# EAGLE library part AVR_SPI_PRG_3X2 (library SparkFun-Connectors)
AVR ISP 6 Pin This is the reduced ISP connector for AVR programming. Common on Arduino. This footprint will take up less PCB space and can be used with a 10-pin to 6-pin adapter such as SKU: BOB-08508 **Special note about "TEST_POINT" package. The stop mask is on the top side, so if you want your programming test points to be on the bottom of your board, make sure to place this package on the bottom side of the board. This also ensure that the orientation to program from the bottom side will be correct.

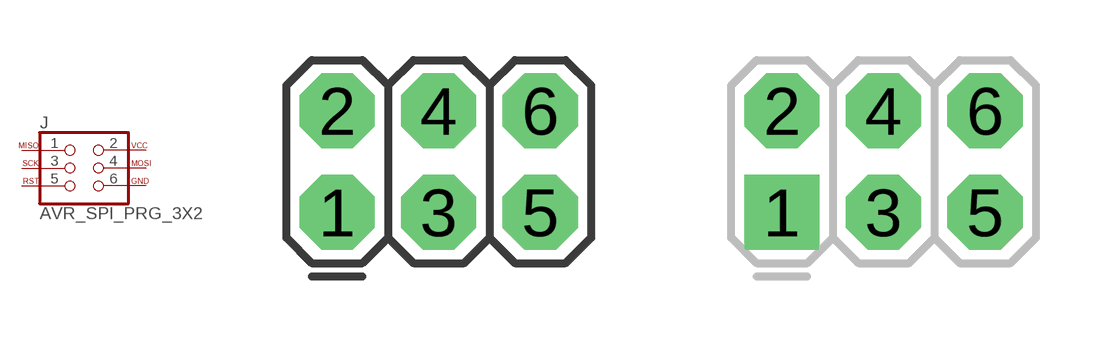
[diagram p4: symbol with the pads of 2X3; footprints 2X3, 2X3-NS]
Designator prefix J

## AVR_SPI_PRG_3X2PTH  [2X3]
1  1  pas
2  2  pas
3  3  pas
4  4  pas
5  5  pas
6  6  pas

## AVR_SPI_PRG_3X2NS  [2X3-NS]
Pads as for 2X3

## AVR_SPI_PRG_3X2OFFSET_PADS  [2X3_OFFSET]
Pads as for 2X3

## AVR_SPI_PRG_3X22X3_LOCK  [2X3_LOCK]
Pads as for 2X3

## AVR_SPI_PRG_3X2TESTPOINTS  [2X3_TEST_POINTS]
Pads as for 2X3

## Footprint 2X3 (pad centres in mm)
drill 1.016 pad 1.88 octagon: 1 0,0; 2 0,2.54; 3 2.54,0; 4 2.54,2.54; 5 5.08,0; 6 5.08,2.54

## Footprint 2X3-NS (pad centres in mm)
drill 1.016 pad 1.88 square: 1 -2.54,-1.27
drill 1.016 pad 1.88 octagon: 2 -2.54,1.27; 3 0,-1.27; 4 0,1.27; 5 2.54,-1.27; 6 2.54,1.27

## Footprint 2X3_OFFSET (pad centres in mm)
drill 1.118 pad 1.88 offset: 1 -2.54,-1.27; 2 -2.54,1.27; 3 0,-1.27; 4 0,1.27; 5 2.54,-1.27; 6 2.54,1.27

## Footprint 2X3_LOCK (pad centres in mm)
drill 1.016 pad 1.88 octagon: 1 0,0; 2 0,2.54; 3 2.54,-0.254; 4 2.54,2.286; 5 5.08,0; 6 5.08,2.54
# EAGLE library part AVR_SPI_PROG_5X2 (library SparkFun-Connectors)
AVR 10-pin ICSP Header This is the standard AVR In Circuit Serial Programming header. Minimal, but includes pin one indicator. Works with standard Olimex programmers. Also look for the 6-pin reduced version. Spark Fun Electronics SKU: PRT-00778

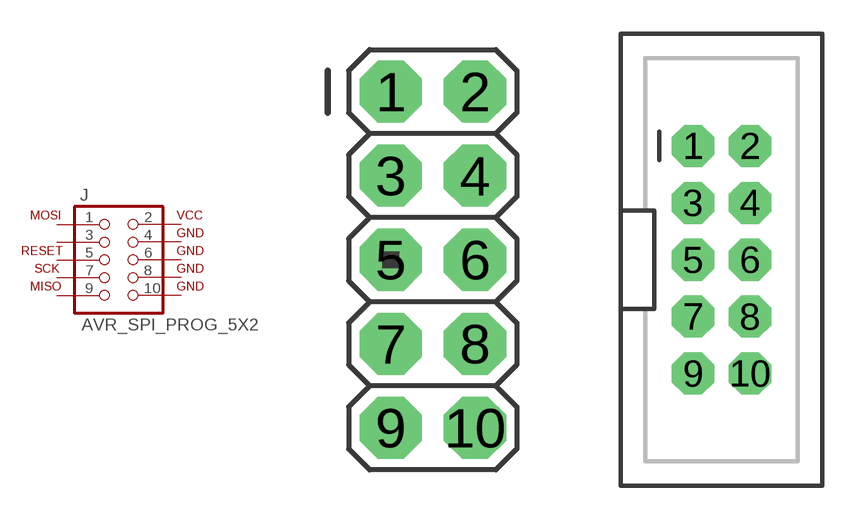
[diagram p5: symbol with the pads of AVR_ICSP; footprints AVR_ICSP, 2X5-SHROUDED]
Designator prefix J

## AVR_SPI_PROG_5X2PTH  [AVR_ICSP]
1  MOSI  pas
2  VCC  pwr
3  NC  nc
4  GND  pwr
5  RESET  pas
6  GND  pwr
7  SCK  pas
8  GND  pwr
9  MISO  pas
10  GND  pwr

## AVR_SPI_PROG_5X2PTH2  [2X5-SHROUDED]
Pads as for AVR_ICSP

## AVR_SPI_PROG_5X2LOCK  [2X5-SHROUDED_LOCK]
Pads as for AVR_ICSP

## AVR_SPI_PROG_5X2SMD  [2X5-SHROUDED_SMD]
Pads as for AVR_ICSP

## Footprint AVR_ICSP (pad centres in mm)
PIN HEADER
drill 1.016 pad 1.88 octagon: 1 -1.27,5.08; 2 1.27,5.08; 3 -1.27,2.54; 4 1.27,2.54; 5 -1.27,0; 6 1.27,0; 7 -1.27,-2.54; 8 1.27,-2.54; 9 -1.27,-5.08; 10 1.27,-5.08

## Footprint 2X5-SHROUDED (pad centres in mm)
drill 1.016 pad 1.88 octagon: 1 -1.27,5.08; 2 1.27,5.08; 3 -1.27,2.54; 4 1.27,2.54; 5 -1.27,0; 6 1.27,0; 7 -1.27,-2.54; 8 1.27,-2.54; 9 -1.27,-5.08; 10 1.27,-5.08

## Footprint 2X5-SHROUDED_LOCK (pad centres in mm)
drill 1.016 pad 1.88 octagon: 1 -1.397,5.08; 2 1.397,5.08; 3 -1.397,2.54; 4 1.397,2.54; 5 -1.397,0; 6 1.397,0; 7 -1.397,-2.54; 8 1.397,-2.54; 9 -1.397,-5.08; 10 1.397,-5.08

## Footprint 2X5-SHROUDED_SMD (pad centres in mm)
smd 4.15 x 1: 1 -2.794,5.08; 2 2.794,5.08; 3 -2.794,2.54; 4 2.794,2.54; 5 -2.794,0; 6 2.794,0; 7 -2.794,-2.54; 8 2.794,-2.54; 9 -2.794,-5.08; 10 2.794,-5.08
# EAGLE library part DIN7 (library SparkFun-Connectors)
Mini-DIN7 connector

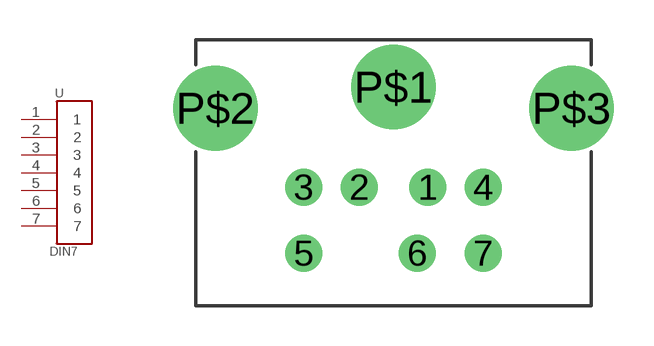
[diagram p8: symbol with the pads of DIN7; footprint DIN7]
Designator prefix -

## DIN7  [DIN7]
1  1
2  2
3  3
4  4
5  5
6  6
7  7

## Footprint DIN7 (pad centres in mm)
drill 0.9: 1 1.3,-3.8; 2 -1.3,-3.8; 3 -3.4,-3.8; 4 3.4,-3.8; 5 -3.4,-6.3; 6 0.9,-6.3; 7 3.4,-6.3
drill 2.2: P$1 0,0; P$2 -6.75,-0.8; P$3 6.75,-0.8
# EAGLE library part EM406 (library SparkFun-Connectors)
EM406 GPS Connector Proven layout and schematic for EM406 connector. Spark Fun Electronics SKU : GPS-00579

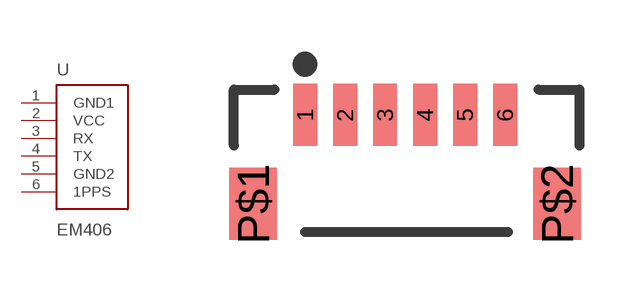
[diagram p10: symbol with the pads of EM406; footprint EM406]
Designator prefix U

## EM406  [EM406]
1  GND1
2  VCC
3  RX
4  TX
5  GND2
6  1PPS

## Footprint EM406 (pad centres in mm)
smd 0.6 x 1.55: 1 0,0; 2 1,0; 3 2,0; 4 3,0; 5 4,0; 6 5,0
smd 1.2 x 1.8: P$1 -1.3,-2.225; P$2 6.3,-2.225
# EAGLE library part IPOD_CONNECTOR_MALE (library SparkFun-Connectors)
iPod Male Connector This is the connector that will insert into an iPods. Use this connector to gain access to the various iPod pins. Schematic and footprint are not yet production proven. The PCB thickness must be more thin than the standard 0.062" FR4. Spark Fun Electronics SKU : DEV-00633

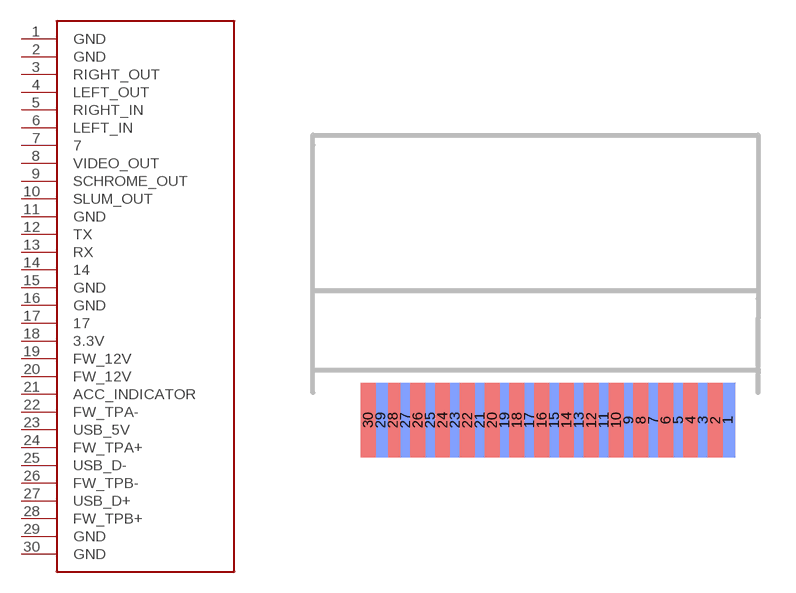
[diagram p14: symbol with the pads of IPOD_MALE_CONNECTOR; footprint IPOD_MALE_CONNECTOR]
Designator prefix -

## IPOD_CONNECTOR_MALE  [IPOD_MALE_CONNECTOR]
1  GND
2  GND
3  RIGHT_OUT
4  LEFT_OUT
5  RIGHT_IN
6  LEFT_IN
7  7
8  VIDEO_OUT
9  SCHROME_OUT
10  SLUM_OUT
11  GND
12  TX
13  RX
14  14
15  GND
16  GND
17  17
18  3.3V
19  FW_12V
20  FW_12V
21  ACC_INDICATOR
22  FW_TPA-
23  USB_5V
24  FW_TPA+
25  USB_D-
26  FW_TPB-
27  USB_D+
28  FW_TPB+
29  GND
30  GND

## Footprint IPOD_MALE_CONNECTOR (pad centres in mm)
smd 0.6 x 3 bottom: 1 7.5,0; 3 6.5,0; 5 5.5,0; 7 4.5,0; 9 3.5,0; 11 2.5,0; 13 1.5,0; 15 0.5,0; 17 -0.5,0; 19 -1.5,0; 21 -2.5,0; 23 -3.5,0; 25 -4.5,0; 27 -5.5,0; 29 -6.5,0
smd 0.6 x 3: 2 7,0; 4 6,0; 6 5,0; 8 4,0; 10 3,0; 12 2,0; 14 1,0; 16 0,0; 18 -1,0; 20 -2,0; 22 -3,0; 24 -4,0; 26 -5,0; 28 -6,0; 30 -7,0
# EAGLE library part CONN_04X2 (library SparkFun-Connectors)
.1" header, two rows of four.

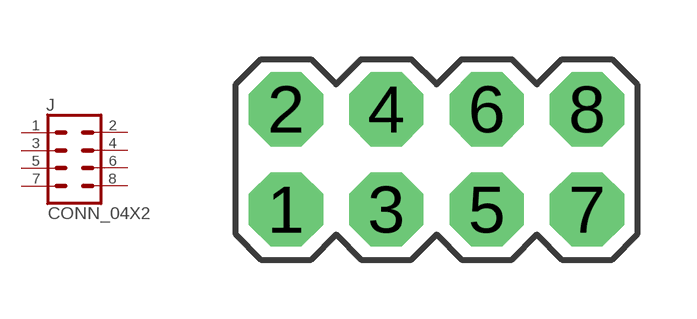
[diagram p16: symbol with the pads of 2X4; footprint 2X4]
Designator prefix J

## CONN_04X2  [2X4]
1  1  pas
2  2  pas
3  3  pas
4  4  pas
5  5  pas
6  6  pas
7  7  pas
8  8  pas

## Footprint 2X4 (pad centres in mm)
drill 1.016 pad 1.88 octagon: 1 -3.81,-1.27; 2 -3.81,1.27; 3 -1.27,-1.27; 4 -1.27,1.27; 5 1.27,-1.27; 6 1.27,1.27; 7 3.81,-1.27; 8 3.81,1.27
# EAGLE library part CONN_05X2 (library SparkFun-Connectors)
Header 5x2 Standard 10-pin dual row 0.1" header. Commonly used with AVR-ISP. Use with Spark Fun Electronics SKU: PRT-00778

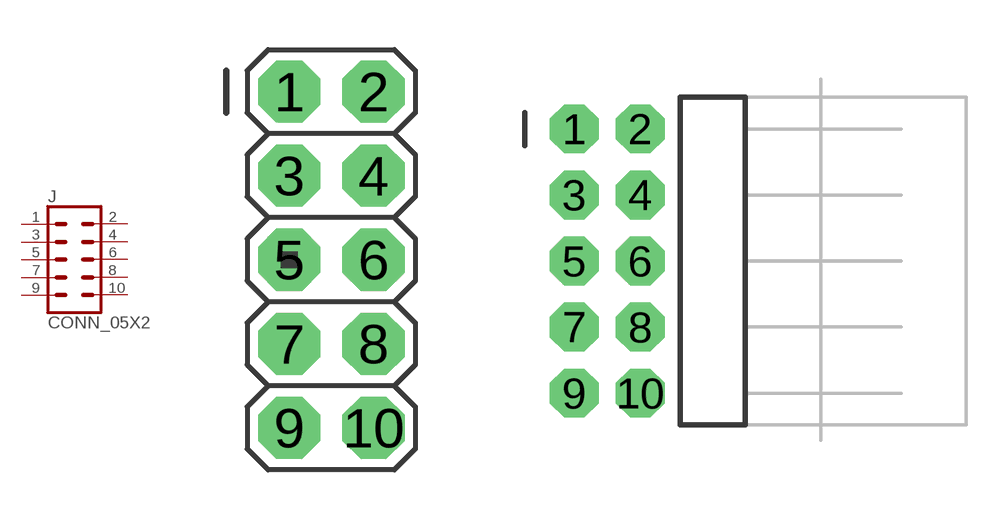
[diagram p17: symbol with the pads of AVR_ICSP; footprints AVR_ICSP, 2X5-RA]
Designator prefix J

## CONN_05X2PTH  [AVR_ICSP]
1  1  pas
2  2  pas
3  3  pas
4  4  pas
5  5  pas
6  6  pas
7  7  pas
8  8  pas
9  9  pas
10  10  pas

## CONN_05X2RA  [2X5-RA]
Pads as for AVR_ICSP

## CONN_05X2RAF  [2X5-RAF]
Pads as for AVR_ICSP

## CONN_05X2SHD  [2X5-SHROUDED]
Pads as for AVR_ICSP

## CONN_05X2SHD_LOCK  [2X5-SHROUDED_LOCK]
Pads as for AVR_ICSP

## CONN_05X2SHD_SMD  [2X5-SHROUDED_SMD]
Pads as for AVR_ICSP

## CONN_05X2NO_SILK  [2X5_NOSILK]
Pads as for AVR_ICSP

## CONN_05X20.05_IN_PTH_SILK  [2X5_PTH_SILK_.05]
Pads as for AVR_ICSP

## CONN_05X2SHD-NS  [2X5-SHROUDED-NS]
Pads as for AVR_ICSP

## Footprint AVR_ICSP (pad centres in mm)
PIN HEADER
drill 1.016 pad 1.88 octagon: 1 -1.27,5.08; 2 1.27,5.08; 3 -1.27,2.54; 4 1.27,2.54; 5 -1.27,0; 6 1.27,0; 7 -1.27,-2.54; 8 1.27,-2.54; 9 -1.27,-5.08; 10 1.27,-5.08

## Footprint 2X5-RA (pad centres in mm)
drill 1.016 pad 1.88 octagon: 1 -1.27,5.08; 2 1.27,5.08; 3 -1.27,2.54; 4 1.27,2.54; 5 -1.27,0; 6 1.27,0; 7 -1.27,-2.54; 8 1.27,-2.54; 9 -1.27,-5.08; 10 1.27,-5.08

## Footprint 2X5-RAF (pad centres in mm)
drill 1.016 pad 1.88 octagon: 1 -1.27,5.08; 2 1.27,5.08; 3 -1.27,2.54; 4 1.27,2.54; 5 -1.27,0; 6 1.27,0; 7 -1.27,-2.54; 8 1.27,-2.54; 9 -1.27,-5.08; 10 1.27,-5.08

## Footprint 2X5-SHROUDED (pad centres in mm)
drill 1.016 pad 1.88 octagon: 1 -1.27,5.08; 2 1.27,5.08; 3 -1.27,2.54; 4 1.27,2.54; 5 -1.27,0; 6 1.27,0; 7 -1.27,-2.54; 8 1.27,-2.54; 9 -1.27,-5.08; 10 1.27,-5.08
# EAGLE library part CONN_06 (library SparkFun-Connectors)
Header 6 Standard 6-pin 0.1" header. Use with straight break away headers (SKU : PRT-00116), right angle break away headers (PRT-00553), swiss pins (PRT-00743), machine pins (PRT-00117), and female headers (PRT-00115). Molex polarized connector foot print use with SKU : PRT-08094 with associated crimp pins and housings. NOTES ON THE VARIANTS LOCK and LOCK_LONGPADS... This footprint was designed to help hold the alignment of a through-hole component (i.e. 6-pin header) while soldering it into place. You may notice that each hole has been shifted either up or down by 0.005 of an inch from it's more standard position (which is a perfectly straight line). This slight alteration caused the pins (the squares in the middle) to touch the edges of the holes. Because they are alternating, it causes a "brace" to hold the component in place. 0.005 has proven to be the perfect amount of "off-center" position when using our standard breakaway headers. Although looks a little odd when you look at the bare footprint, once you have a header in there, the alteration is very hard to notice. Also,if you push a header all the way into place, it is covered up entirely on the bottom side. This idea of altering the position of holes to aid alignment will be further integrated into the Sparkfun Library for other footprints. It can help hold any component with 3 or more connection pins.

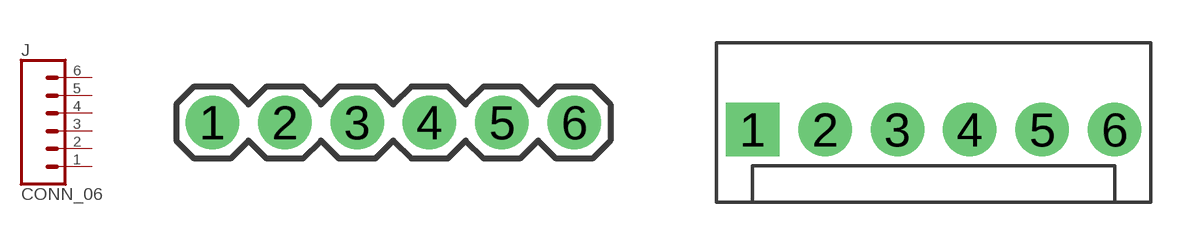
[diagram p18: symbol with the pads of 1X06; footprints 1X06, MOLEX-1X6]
Designator prefix J

## CONN_06SILK_FEMALE_PTH (PROD_ID: CONN-08437)  [1X06]
1  1  pas
2  2  pas
3  3  pas
4  4  pas
5  5  pas
6  6  pas

## CONN_06POLAR  [MOLEX-1X6]
Pads as for 1X06

## CONN_06RA  [MOLEX-1X6-RA]
Pads as for 1X06

## CONN_06SMD (PROD_ID: CONN-08971; VALUE: RA 6Pin SMD)  [1X06-SMD]
Pads as for 1X06

## CONN_06LOCK  [1X06_LOCK]
Pads as for 1X06

## CONN_06LOCK_LONGPADS  [1X06_LOCK_LONGPADS]
Pads as for 1X06

## CONN_06POLAR_LOCK  [MOLEX-1X6_LOCK]
Pads as for 1X06

## CONN_06RA_LOCK  [MOLEX-1X6-RA_LOCK]
Pads as for 1X06

## CONN_06SIP_LOCK  [1X06-SIP_LOCK]
Pads as for 1X06

## CONN_06FEMALE_LOCK  [1X06_FEMALE_LOCK.010]
Pads as for 1X06

## CONN_06LONGPADS  [1X06_LONGPADS]
Pads as for 1X06

## CONN_061X06-SMD_EDGE_FEMALE  [1X06-SMD_EDGE]
Pads as for 1X06

## CONN_063.5MM-6  [SCREWTERMINAL-3.5MM-6]
Pads as for 1X06

## CONN_06SMDF  [1X06-SMD-FEMALE]
Pads as for 1X06

## CONN_06SMD-FEMALE-V2 (PROD_ID: CONN-09668)  [1X06-SMD-FEMALE-V2]
Pads as for 1X06

## CONN_06POGOPIN_HOLES_ONLY (PROD_ID: CONN-08437)  [1X06_HOLES_ONLY]
Pads as for 1X06

## CONN_06SMD-STRAIGHT-FEMALE (PROD_ID: CONN-10203)  [1X06_SMD_STRAIGHT]
Pads as for 1X06

## CONN_06SMD-STRAIGHT-ALT-FEMALE (PROD_ID: CONN-10203)  [1X06_SMD_STRAIGHT_ALT]
Pads as for 1X06

## CONN_06SMD-STRAIGHT-COMBO-FEMALE (PROD_ID: CONN-10203)  [1X06_SMD_STRAIGHT_COMBO]
Pads as for 1X06

## CONN_06VERNIER-ANALOG  [BTA]
Pads as for 1X06

## CONN_06VERNIER-DIGITAL  [BTD]
Pads as for 1X06

## CONN_06SMD_MALE (PROD_ID: CONN-11293)  [1X06_SMD_MALE]
Pads as for 1X06

## CONN_06SMD-1MM  [1X06-1MM]
Pads as for 1X06

## CONN_06NO_SILK_FEMALE_PTH (PROD_ID: CONN-08437)  [1X06_NO_SILK]
Pads as for 1X06

## CONN_06NO_SILK_YES_STOP  [1X06_NO_SILK_YES_STOP]
Pads as for 1X06

## CONN_061.27MM  [1X06-1.27MM]
Pads as for 1X06

## Footprint 1X06 (pad centres in mm)
drill 1.016 pad 1.88: 1 0,0; 2 2.54,0; 3 5.08,0; 4 7.62,0; 5 10.16,0; 6 12.7,0

## Footprint MOLEX-1X6 (pad centres in mm)
drill 1.016 pad 1.88 square: 1 0,0
drill 1.016 pad 1.88: 2 2.54,0; 3 5.08,0; 4 7.62,0; 5 10.16,0; 6 12.7,0

## Footprint MOLEX-1X6-RA (pad centres in mm)
drill 1.016 pad 1.88 square: 1 0,0
drill 1.016 pad 1.88: 2 2.54,0; 3 5.08,0; 4 7.62,0; 5 10.16,0; 6 12.7,0

## Footprint 1X06-SMD (pad centres in mm)
smd 1 x 3: 1 -6.35,5; 2 -3.81,5; 3 -1.27,5; 4 1.27,5; 5 3.81,5; 6 6.35,5
hole 1.4 at -5.08,0
hole 1.4 at 5.08,0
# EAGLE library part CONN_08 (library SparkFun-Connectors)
Header 8 Standard 8-pin 0.1" header. Use with straight break away headers (SKU : PRT-00116), right angle break away headers (PRT-00553), swiss pins (PRT-00743), machine pins (PRT-00117), and female headers (PRT-00115).

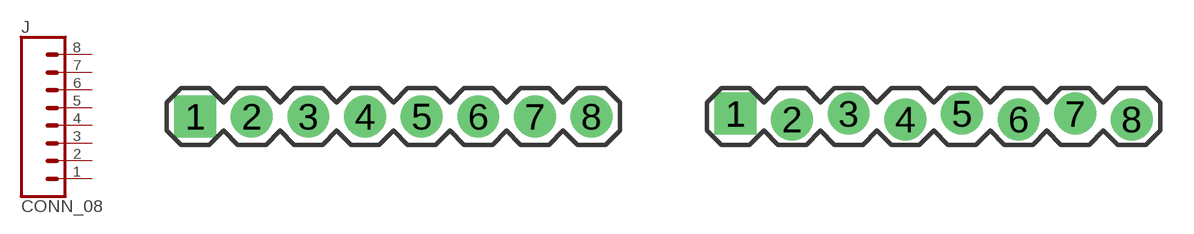
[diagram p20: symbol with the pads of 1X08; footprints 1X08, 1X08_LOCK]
Designator prefix J

## CONN_08SILK_FEMALE_PTH (PROD_ID: CONN-08438)  [1X08]
1  1  pas
2  2  pas
3  3  pas
4  4  pas
5  5  pas
6  6  pas
7  7  pas
8  8  pas

## CONN_08LOCK  [1X08_LOCK]
Pads as for 1X08

## CONN_08LOCK_LONGPADS  [1X08_LOCK_LONGPADS]
Pads as for 1X08

## CONN_08LONGPADS  [1X08_LONGPADS]
Pads as for 1X08

## CONN_083.5MM-8  [SCREWTERMINAL-3.5MM-8]
Pads as for 1X08

## CONN_08SMD-STRAIGHT-FEMALE (PROD_ID: CONN-10204)  [1X08_SMD]
Pads as for 1X08

## CONN_08SMD-STRAIGHT-ALT-FEMALE (PROD_ID: CONN-10204)  [1X08_SMD_ALT]
Pads as for 1X08

## CONN_08SMD-COMBO-FEMALE (PROD_ID: CONN-10204)  [1X08_SMD_COMBINED]
Pads as for 1X08

## CONN_08BM08B-SRSS-TB  [BM08B-SRSS-TB]
Pads as for 1X08

## CONN_08SMD-MALE (PROD_ID: CONN-11292)  [1X08_SMD_MALE]
Pads as for 1X08

## CONN_08NO_SILK_FEMALE_PTH (PROD_ID: CONN-08438)  [1X08_NO_SILK]
Pads as for 1X08

## CONN_08NO_SILK  [1X08_PIN1_NO_SILK]
Pads as for 1X08

## CONN_08 (PROD_ID: CONN-08437)  [1X08_ROUND]
Pads as for 1X08

## CONN_08LOCK_NO_SILK  [1X08_LOCK_NO_SILK]
Pads as for 1X08

## CONN_08FEMALE_LOCK  [1X08_FEMALE_LOCK]
Pads as for 1X08

## Footprint 1X08 (pad centres in mm)
drill 1.016 pad 1.88 square: 1 0,0
drill 1.016 pad 1.88: 2 2.54,0; 3 5.08,0; 4 7.62,0; 5 10.16,0; 6 12.7,0; 7 15.24,0; 8 17.78,0

## Footprint 1X08_LOCK (pad centres in mm)
drill 1.016 pad 1.88 square: 1 0,0.127
drill 1.016 pad 1.88: 2 2.54,-0.127; 3 5.08,0.127; 4 7.62,-0.127; 5 10.16,0.127; 6 12.7,-0.127; 7 15.24,0.127; 8 17.78,-0.127

## Footprint 1X08_LOCK_LONGPADS (pad centres in mm)
drill 1.016 long: 1 0,0.127; 2 2.54,-0.127; 3 5.08,0.127; 4 7.62,-0.127; 5 10.16,0.127; 6 12.7,-0.127; 7 15.24,0.127; 8 17.78,-0.127

## Footprint 1X08_LONGPADS (pad centres in mm)
drill 1.118 pad 1.88 long: 1 0,0; 2 2.54,0; 3 5.08,0; 4 7.62,0; 5 10.16,0; 6 12.7,0; 7 15.24,0; 8 17.78,0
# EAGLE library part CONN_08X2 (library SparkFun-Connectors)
.1" headers, two rows of 8 each

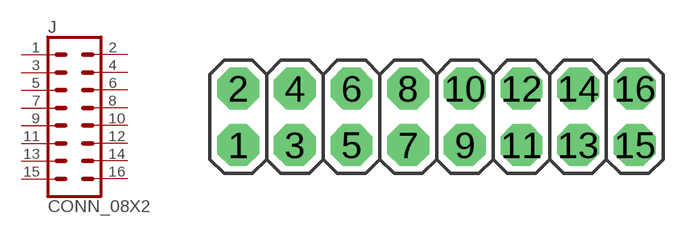
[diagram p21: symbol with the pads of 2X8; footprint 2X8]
Designator prefix J

## CONN_08X2  [2X8]
1  1  pas
2  2  pas
3  3  pas
4  4  pas
5  5  pas
6  6  pas
7  7  pas
8  8  pas
9  9  pas
10  10  pas
11  11  pas
12  12  pas
13  13  pas
14  14  pas
15  15  pas
16  16  pas

## Footprint 2X8 (pad centres in mm)
drill 1.016 pad 1.88 octagon: 1 0,0; 2 0,2.54; 3 2.54,0; 4 2.54,2.54; 5 5.08,0; 6 5.08,2.54; 7 7.62,0; 8 7.62,2.54; 9 10.16,0; 10 10.16,2.54; 11 12.7,0; 12 12.7,2.54; 13 15.24,0; 14 15.24,2.54; 15 17.78,0; 16 17.78,2.54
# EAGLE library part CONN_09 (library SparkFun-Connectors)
Header 9 Standard 9-pin 0.1" header. Use with straight break away headers (SKU : PRT-00116), right angle break away headers (PRT-00553), swiss pins (PRT-00743), machine pins (PRT-00117), and female headers (PRT-00115).

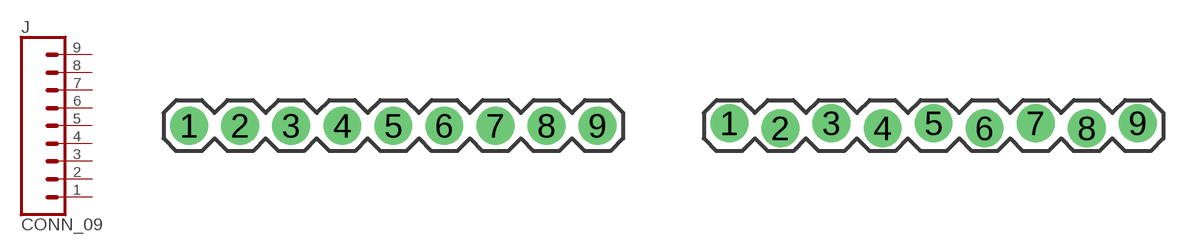
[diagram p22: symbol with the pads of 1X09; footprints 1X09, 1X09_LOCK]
Designator prefix J

## CONN_09  [1X09]
1  1  pas
2  2  pas
3  3  pas
4  4  pas
5  5  pas
6  6  pas
7  7  pas
8  8  pas
9  9  pas

## CONN_09LOCK  [1X09_LOCK]
Pads as for 1X09

## CONN_09LOCK-LONGPADS  [1X09_LOCK_LONGPADS]
Pads as for 1X09

## CONN_09LONGPADS  [1X09_LONGPADS]
Pads as for 1X09

## CONN_09NO_SILK  [1X09_NO_SILK]
Pads as for 1X09

## Footprint 1X09 (pad centres in mm)
drill 1.016 pad 1.88: 1 0,0; 2 2.54,0; 3 5.08,0; 4 7.62,0; 5 10.16,0; 6 12.7,0; 7 15.24,0; 8 17.78,0; 9 20.32,0

## Footprint 1X09_LOCK (pad centres in mm)
drill 1.016 pad 1.88: 1 0,0.127; 2 2.54,-0.127; 3 5.08,0.127; 4 7.62,-0.127; 5 10.16,0.127; 6 12.7,-0.127; 7 15.24,0.127; 8 17.78,-0.127; 9 20.32,0.127

## Footprint 1X09_LOCK_LONGPADS (pad centres in mm)
drill 1.016 long: 1 0,0.127; 2 2.54,-0.127; 3 5.08,0.127; 4 7.62,-0.127; 5 10.16,0.127; 6 12.7,-0.127; 7 15.24,0.127; 8 17.78,-0.127; 9 20.32,0.127

## Footprint 1X09_LONGPADS (pad centres in mm)
drill 1.118 pad 1.88 long: 1 0,0; 2 2.54,0; 3 5.08,0; 4 7.62,0; 5 10.16,0; 6 12.7,0; 7 15.24,0; 8 17.78,0; 9 20.32,0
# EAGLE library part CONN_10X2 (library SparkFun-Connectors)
This was SPECIALLY designed to be used with our Graphic LCD Backpack. Be sure you want to use this! It is not only staggered on each line of header holes, but IT IS ALSO offset of the center point of the top and bottom lines by 5 mil. This causes the headers to lock into place on the "standard" footprint on the LCD screen. The extra squares on the tdocu layer are there simply to reference other pins (if you were to actually populate a longer header than ten long - this is what we do with the backpacks).

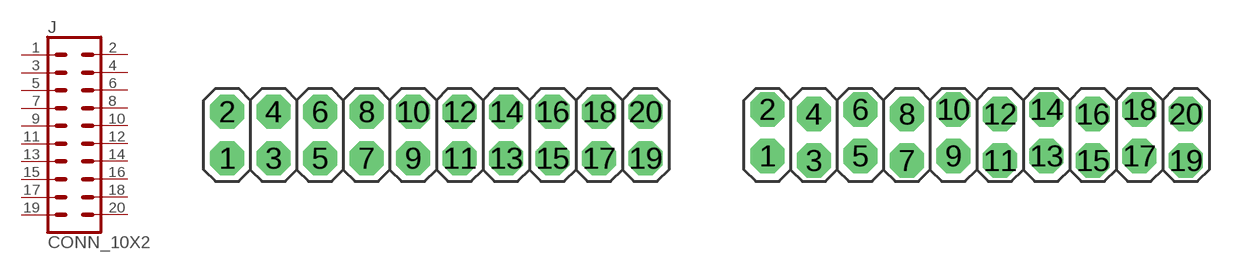
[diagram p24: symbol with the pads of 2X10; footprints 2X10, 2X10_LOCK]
Designator prefix J

## CONN_10X2  [2X10]
1  1  pas
2  2  pas
3  3  pas
4  4  pas
5  5  pas
6  6  pas
7  7  pas
8  8  pas
9  9  pas
10  10  pas
11  11  pas
12  12  pas
13  13  pas
14  14  pas
15  15  pas
16  16  pas
17  17  pas
18  18  pas
19  19  pas
20  20  pas

## CONN_10X22X10_LOCK  [2X10_LOCK]
Pads as for 2X10

## CONN_10X2SPECIAL  [2X10_LOCK_SPECIAL]
Pads as for 2X10

## CONN_10X2NOSILK  [2X10_NOSILK]
Pads as for 2X10

## CONN_10X2ROUND_NOSILK  [2X10_ROUND_NOSILK]
Pads as for 2X10

## Footprint 2X10 (pad centres in mm)
PIN HEADER
drill 1.016 pad 1.88 octagon: 1 -11.43,-1.27; 2 -11.43,1.27; 3 -8.89,-1.27; 4 -8.89,1.27; 5 -6.35,-1.27; 6 -6.35,1.27; 7 -3.81,-1.27; 8 -3.81,1.27; 9 -1.27,-1.27; 10 -1.27,1.27; 11 1.27,-1.27; 12 1.27,1.27; 13 3.81,-1.27; 14 3.81,1.27; 15 6.35,-1.27; 16 6.35,1.27; 17 8.89,-1.27; 18 8.89,1.27; 19 11.43,-1.27; 20 11.43,1.27

## Footprint 2X10_LOCK (pad centres in mm)
PIN HEADER
drill 1.016 pad 1.88 octagon: 1 -11.43,-1.143; 2 -11.43,1.397; 3 -8.89,-1.397; 4 -8.89,1.143; 5 -6.35,-1.143; 6 -6.35,1.397; 7 -3.81,-1.397; 8 -3.81,1.143; 9 -1.27,-1.143; 10 -1.27,1.397; 11 1.27,-1.397; 12 1.27,1.143; 13 3.81,-1.143; 14 3.81,1.397; 15 6.35,-1.397; 16 6.35,1.143; 17 8.89,-1.143; 18 8.89,1.397; 19 11.43,-1.397; 20 11.43,1.143

## Footprint 2X10_LOCK_SPECIAL (pad centres in mm)
PIN HEADER
drill 1.016 pad 1.88 octagon: 1 -11.43,-1.422; 2 -11.43,1.676; 3 -8.89,-1.676; 4 -8.89,1.422; 5 -6.35,-1.422; 6 -6.35,1.676; 7 -3.81,-1.676; 8 -3.81,1.422; 9 -1.27,-1.422; 10 -1.27,1.676; 11 1.27,-1.676; 12 1.27,1.422; 13 3.81,-1.422; 14 3.81,1.676; 15 6.35,-1.676; 16 6.35,1.422; 17 8.89,-1.422; 18 8.89,1.676; 19 11.43,-1.676; 20 11.43,1.422

## Footprint 2X10_NOSILK (pad centres in mm)
drill 1.016 pad 1.88 octagon: 1 -11.43,-1.27; 2 -11.43,1.27; 3 -8.89,-1.27; 4 -8.89,1.27; 5 -6.35,-1.27; 6 -6.35,1.27; 7 -3.81,-1.27; 8 -3.81,1.27; 9 -1.27,-1.27; 10 -1.27,1.27; 11 1.27,-1.27; 12 1.27,1.27; 13 3.81,-1.27; 14 3.81,1.27; 15 6.35,-1.27; 16 6.35,1.27; 17 8.89,-1.27; 18 8.89,1.27; 19 11.43,-1.27; 20 11.43,1.27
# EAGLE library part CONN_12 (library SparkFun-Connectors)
Header 12 Standard 12-pin 0.1" header. Use with straight break away headers (SKU : PRT-00116), right angle break away headers (PRT-00553), swiss pins (PRT-00743), machine pins (PRT-00117), and female headers (PRT-00115).

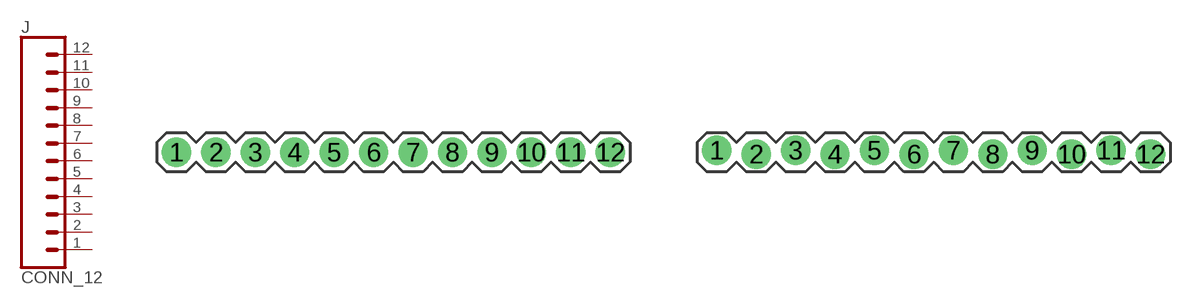
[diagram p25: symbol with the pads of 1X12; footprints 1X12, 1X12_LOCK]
Designator prefix J

## CONN_12PTH  [1X12]
1  1  pas
2  2  pas
3  3  pas
4  4  pas
5  5  pas
6  6  pas
7  7  pas
8  8  pas
9  9  pas
10  10  pas
11  11  pas
12  12  pas

## CONN_12LOCK  [1X12_LOCK]
Pads as for 1X12

## CONN_12LOCK_LONGPADS  [1X12_LOCK_LONGPADS]
Pads as for 1X12

## CONN_12MACHINE-PIN_LOCK  [1X12_MACHINE-PIN-HEADER_LOCK.004]
Pads as for 1X12

## CONN_12LONGPADS  [1X12_LONGPADS]
Pads as for 1X12

## CONN_12POGOPIN_HOLES_ONLY  [1X12_HOLES_ONLY]
Pads as for 1X12

## CONN_121X12_NO_SILK_KIT  [1X12_NO_SILK_KIT]
Pads as for 1X12

## CONN_12NO_SILK  [1X12_NO_SILK]
Pads as for 1X12

## CONN_12LOCK_NO_SILK  [1X12_LOCK_NO_SILK]
Pads as for 1X12

## Footprint 1X12 (pad centres in mm)
drill 1.016 pad 1.88: 1 0,0; 2 2.54,0; 3 5.08,0; 4 7.62,0; 5 10.16,0; 6 12.7,0; 7 15.24,0; 8 17.78,0; 9 20.32,0; 10 22.86,0; 11 25.4,0; 12 27.94,0

## Footprint 1X12_LOCK (pad centres in mm)
drill 1.016 pad 1.88: 1 0,0.127; 2 2.54,-0.127; 3 5.08,0.127; 4 7.62,-0.127; 5 10.16,0.127; 6 12.7,-0.127; 7 15.24,0.127; 8 17.78,-0.127; 9 20.32,0.127; 10 22.86,-0.127; 11 25.4,0.127; 12 27.94,-0.127

## Footprint 1X12_LOCK_LONGPADS (pad centres in mm)
drill 1.016 long: 1 0,0.127; 2 2.54,-0.127; 3 5.08,0.127; 4 7.62,-0.127; 5 10.16,0.127; 6 12.7,-0.127; 7 15.24,0.127; 8 17.78,-0.127; 9 20.32,0.127; 10 22.86,-0.127; 11 25.4,0.127; 12 27.94,-0.127

## Footprint 1X12_MACHINE-PIN-HEADER_LOCK.004 (pad centres in mm)
drill 0.889 pad 1.88: 1 0,0.102; 2 2.54,-0.102; 3 5.08,0.102; 4 7.62,-0.102; 5 10.16,0.102; 6 12.7,-0.102; 7 15.24,0.102; 8 17.78,-0.102; 9 20.32,0.102; 10 22.86,-0.102; 11 25.4,0.102; 12 27.94,-0.102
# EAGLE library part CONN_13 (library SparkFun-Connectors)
13-pin single row .1" header

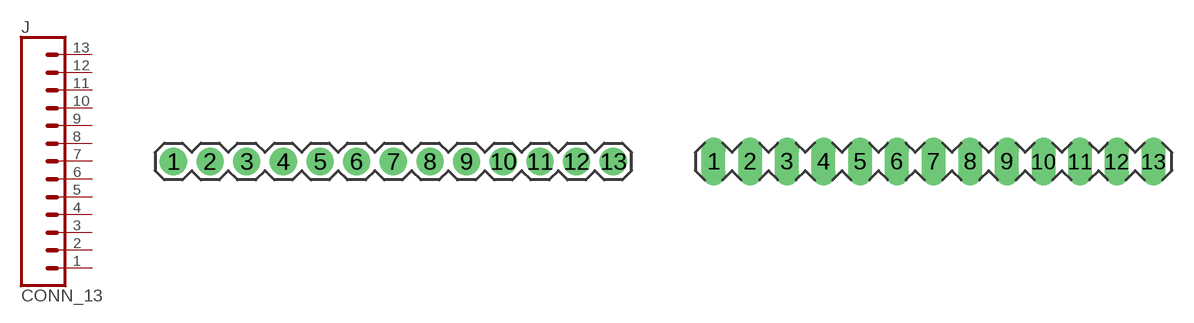
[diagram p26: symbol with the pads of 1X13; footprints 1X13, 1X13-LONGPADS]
Designator prefix J

## CONN_13  [1X13]
1  1  pas
2  2  pas
3  3  pas
4  4  pas
5  5  pas
6  6  pas
7  7  pas
8  8  pas
9  9  pas
10  10  pas
11  11  pas
12  12  pas
13  13  pas

## CONN_13LONGPADS  [1X13-LONGPADS]
Pads as for 1X13

## CONN_13LOCK  [1X13_LOCK]
Pads as for 1X13

## CONN_13LOCK_NO_SILK  [1X13_LOCK_NO_SILK]
Pads as for 1X13

## Footprint 1X13 (pad centres in mm)
drill 1.016 pad 1.88: 1 0,0; 2 2.54,0; 3 5.08,0; 4 7.62,0; 5 10.16,0; 6 12.7,0; 7 15.24,0; 8 17.78,0; 9 20.32,0; 10 22.86,0; 11 25.4,0; 12 27.94,0; 13 30.48,0

## Footprint 1X13-LONGPADS (pad centres in mm)
drill 1.118 long: 1 0,0; 2 2.54,0; 3 5.08,0; 4 7.62,0; 5 10.16,0; 6 12.7,0; 7 15.24,0; 8 17.78,0; 9 20.32,0; 10 22.86,0; 11 25.4,0; 12 27.94,0; 13 30.48,0

## Footprint 1X13_LOCK (pad centres in mm)
drill 1.016 pad 1.88: 1 0,0.127; 2 2.54,-0.127; 3 5.08,0.127; 4 7.62,-0.127; 5 10.16,0.127; 6 12.7,-0.127; 7 15.24,0.127; 8 17.78,-0.127; 9 20.32,0.127; 10 22.86,-0.127; 11 25.4,0.127; 12 27.94,-0.127; 13 30.48,0.127

## Footprint 1X13_LOCK_NO_SILK (pad centres in mm)
drill 1.016 pad 1.88: 1 0,0.127; 2 2.54,-0.127; 3 5.08,0.127; 4 7.62,-0.127; 5 10.16,0.127; 6 12.7,-0.127; 7 15.24,0.127; 8 17.78,-0.127; 9 20.32,0.127; 10 22.86,-0.127; 11 25.4,0.127; 12 27.94,-0.127; 13 30.48,0.127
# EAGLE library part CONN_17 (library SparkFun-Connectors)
1x17 .1" header

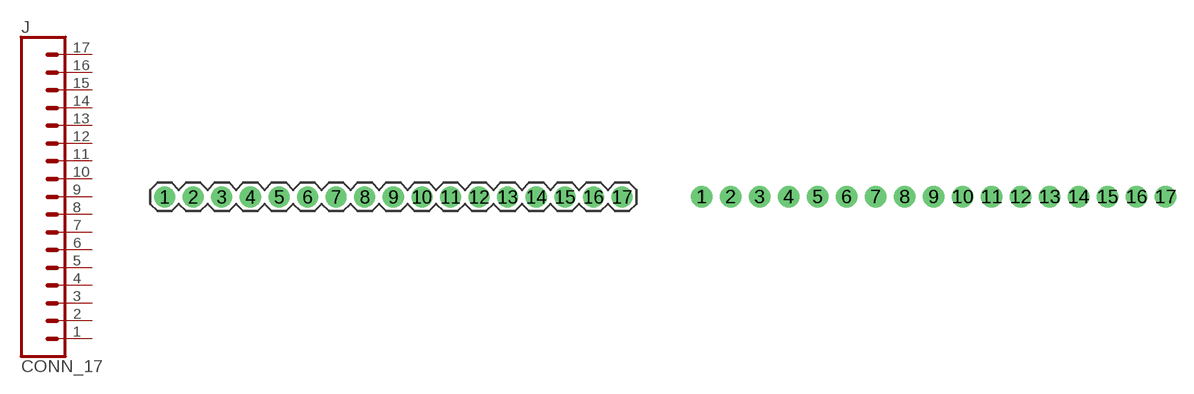
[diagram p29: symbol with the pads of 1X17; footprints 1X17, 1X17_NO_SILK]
Designator prefix J

## CONN_17  [1X17]
1  1  pas
2  2  pas
3  3  pas
4  4  pas
5  5  pas
6  6  pas
7  7  pas
8  8  pas
9  9  pas
10  10  pas
11  11  pas
12  12  pas
13  13  pas
14  14  pas
15  15  pas
16  16  pas
17  17  pas

## CONN_17NOSILK  [1X17_NO_SILK]
Pads as for 1X17

## CONN_17KIT (PROD_ID: CONN-12294)  [1X17_NO_SILK_KIT]
Pads as for 1X17

## Footprint 1X17 (pad centres in mm)
drill 1.016 pad 1.88: 1 0,0; 2 2.54,0; 3 5.08,0; 4 7.62,0; 5 10.16,0; 6 12.7,0; 7 15.24,0; 8 17.78,0; 9 20.32,0; 10 22.86,0; 11 25.4,0; 12 27.94,0; 13 30.48,0; 14 33.02,0; 15 35.56,0; 16 38.1,0; 17 40.64,0

## Footprint 1X17_NO_SILK (pad centres in mm)
drill 1.016 pad 1.88: 1 0,0; 2 2.54,0; 3 5.08,0; 4 7.62,0; 5 10.16,0; 6 12.7,0; 7 15.24,0; 8 17.78,0; 9 20.32,0; 10 22.86,0; 11 25.4,0; 12 27.94,0; 13 30.48,0; 14 33.02,0; 15 35.56,0; 16 38.1,0; 17 40.64,0

## Footprint 1X17_NO_SILK_KIT (pad centres in mm)
drill 1.016 pad 1.88: 1 0,0; 2 2.54,0; 3 5.08,0; 4 7.62,0; 5 10.16,0; 6 12.7,0; 7 15.24,0; 8 17.78,0; 9 20.32,0; 10 22.86,0; 11 25.4,0; 12 27.94,0; 13 30.48,0; 14 33.02,0; 15 35.56,0; 16 38.1,0; 17 40.64,0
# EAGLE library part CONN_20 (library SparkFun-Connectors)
1x20 .1" header This is just like the LOCK variant in that the holes are staggared by 5 mil, but except for the last two holes. They are not altered from the "standard" footprint layout. This is used for a special purpose on the layout of our Graphic LCD Backpack. Make sure you want to use this device before selecting it for you project!

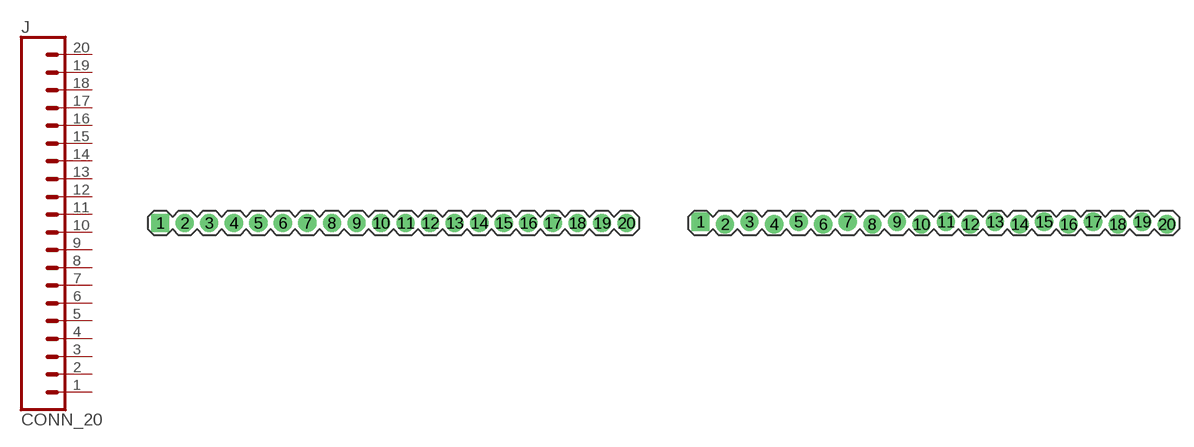
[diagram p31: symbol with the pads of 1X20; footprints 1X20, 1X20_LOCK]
Designator prefix J

## CONN_20  [1X20]
1  1  pas
2  2  pas
3  3  pas
4  4  pas
5  5  pas
6  6  pas
7  7  pas
8  8  pas
9  9  pas
10  10  pas
11  11  pas
12  12  pas
13  13  pas
14  14  pas
15  15  pas
16  16  pas
17  17  pas
18  18  pas
19  19  pas
20  20  pas

## CONN_20LOCK  [1X20_LOCK]
Pads as for 1X20

## CONN_20LOCK_LONGPADS  [1X20_LOCK_LONGPADS]
Pads as for 1X20

## CONN_20SPECIAL  [1X20_LOCK_SPECIAL]
Pads as for 1X20

## CONN_20NO_SILK_KIT  [1X20_NO_SILK_KIT]
Pads as for 1X20

## CONN_20LOCK_NOSILK (PROD_ID: CONN-09864)  [1X20_LOCK_NOSILK]
Pads as for 1X20

## CONN_20NOSILK  [1X20_NOSILK]
Pads as for 1X20

## Footprint 1X20 (pad centres in mm)
drill 1.016 pad 1.88 square: 1 0,0
drill 1.016 pad 1.88: 2 2.54,0; 3 5.08,0; 4 7.62,0; 5 10.16,0; 6 12.7,0; 7 15.24,0; 8 17.78,0; 9 20.32,0; 10 22.86,0; 11 25.4,0; 12 27.94,0; 13 30.48,0; 14 33.02,0; 15 35.56,0; 16 38.1,0; 17 40.64,0; 18 43.18,0; 19 45.72,0; 20 48.26,0

## Footprint 1X20_LOCK (pad centres in mm)
drill 1.016 pad 1.88 square: 1 0,0.127
drill 1.016 pad 1.88: 2 2.54,-0.127; 3 5.08,0.127; 4 7.62,-0.127; 5 10.16,0.127; 6 12.7,-0.127; 7 15.24,0.127; 8 17.78,-0.127; 9 20.32,0.127; 10 22.86,-0.127; 11 25.4,0.127; 12 27.94,-0.127; 13 30.48,0.127; 14 33.02,-0.127; 15 35.56,0.127; 16 38.1,-0.127; 17 40.64,0.127; 18 43.18,-0.127; 19 45.72,0.127; 20 48.26,-0.127

## Footprint 1X20_LOCK_LONGPADS (pad centres in mm)
drill 1.016 long: 1 0,0.127; 2 2.54,-0.127; 3 5.08,0.127; 4 7.62,-0.127; 5 10.16,0.127; 6 12.7,-0.127; 7 15.24,0.127; 8 17.78,-0.127; 9 20.32,0.127; 10 22.86,-0.127; 11 25.4,0.127; 12 27.94,-0.127; 13 30.48,0.127; 14 33.02,-0.127; 15 35.56,0.127; 16 38.1,-0.127; 17 40.64,0.127; 18 43.18,-0.127; 19 45.72,0.127; 20 48.26,-0.127

## Footprint 1X20_LOCK_SPECIAL (pad centres in mm)
drill 1.016 pad 1.88 square: 1 0,0.127
drill 1.016 pad 1.88: 2 2.54,-0.127; 3 5.08,0.127; 4 7.62,-0.127; 5 10.16,0.127; 6 12.7,-0.127; 7 15.24,0.127; 8 17.78,-0.127; 9 20.32,0.127; 10 22.86,-0.127; 11 25.4,0.127; 12 27.94,-0.127; 13 30.48,0.127; 14 33.02,-0.127; 15 35.56,0.127; 16 38.1,-0.127; 17 40.64,0.127; 18 43.18,-0.127; 19 45.593,0; 20 48.387,0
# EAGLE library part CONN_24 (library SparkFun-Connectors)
1x24 .1" header

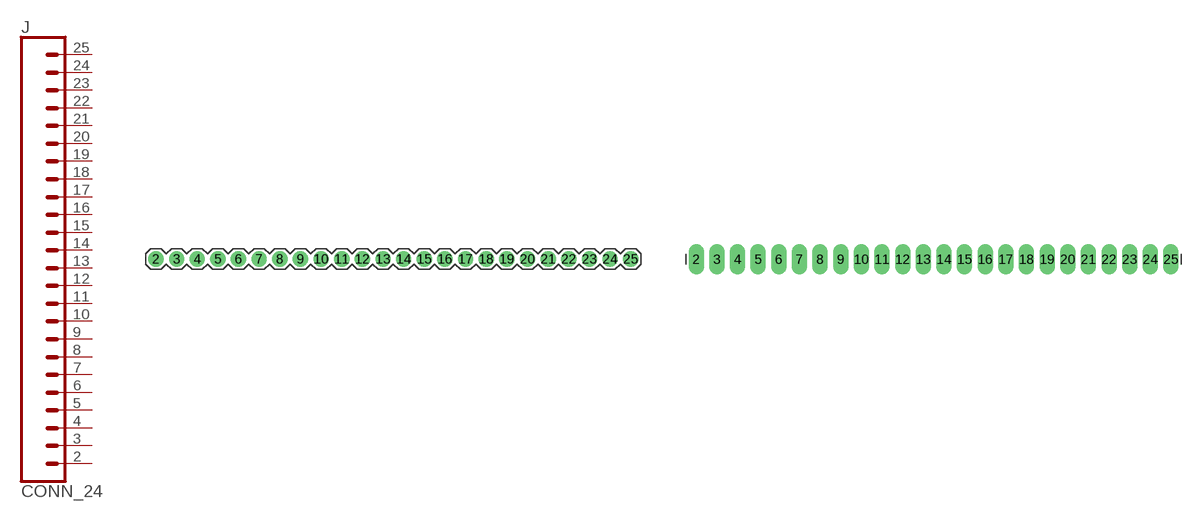
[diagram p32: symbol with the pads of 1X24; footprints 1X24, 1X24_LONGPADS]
Designator prefix J

## CONN_24  [1X24]
2  2  pas
3  3  pas
4  4  pas
5  5  pas
6  6  pas
7  7  pas
8  8  pas
9  9  pas
10  10  pas
11  11  pas
12  12  pas
13  13  pas
14  14  pas
15  15  pas
16  16  pas
17  17  pas
18  18  pas
19  19  pas
20  20  pas
21  21  pas
22  22  pas
23  23  pas
24  24  pas
25  25  pas

## CONN_24LONGPADS  [1X24_LONGPADS]
Pads as for 1X24

## CONN_24LOCK  [1X24_LOCK]
Pads as for 1X24

## Footprint 1X24 (pad centres in mm)
drill 1.016 pad 1.88: 2 -26.67,0; 3 -24.13,0; 4 -21.59,0; 5 -19.05,0; 6 -16.51,0; 7 -13.97,0; 8 -11.43,0; 9 -8.89,0; 10 -6.35,0; 11 -3.81,0; 12 -1.27,0; 13 1.27,0; 14 3.81,0; 15 6.35,0; 16 8.89,0; 17 11.43,0; 18 13.97,0; 19 16.51,0; 20 19.05,0; 21 21.59,0; 22 24.13,0; 23 26.67,0; 24 29.21,0; 25 31.75,0

## Footprint 1X24_LONGPADS (pad centres in mm)
drill 1.118 pad 1.88 long: 2 -26.67,0; 3 -24.13,0; 4 -21.59,0; 5 -19.05,0; 6 -16.51,0; 7 -13.97,0; 8 -11.43,0; 9 -8.89,0; 10 -6.35,0; 11 -3.81,0; 12 -1.27,0; 13 1.27,0; 14 3.81,0; 15 6.35,0; 16 8.89,0; 17 11.43,0; 18 13.97,0; 19 16.51,0; 20 19.05,0; 21 21.59,0; 22 24.13,0; 23 26.67,0; 24 29.21,0; 25 31.75,0

## Footprint 1X24_LOCK (pad centres in mm)
drill 1.016 pad 1.88: 2 -26.67,0.127; 3 -24.13,-0.127; 4 -21.59,0.127; 5 -19.05,-0.127; 6 -16.51,0.127; 7 -13.97,-0.127; 8 -11.43,0.127; 9 -8.89,-0.127; 10 -6.35,0.127; 11 -3.81,-0.127; 12 -1.27,0.127; 13 1.27,-0.127; 14 3.81,0.127; 15 6.35,-0.127; 16 8.89,0.127; 17 11.43,-0.127; 18 13.97,0.127; 19 16.51,-0.127; 20 19.05,0.127; 21 21.59,-0.127; 22 24.13,0.127; 23 26.67,-0.127; 24 29.21,0.127; 25 31.75,-0.127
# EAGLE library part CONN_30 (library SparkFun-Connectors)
1x30 .1" header

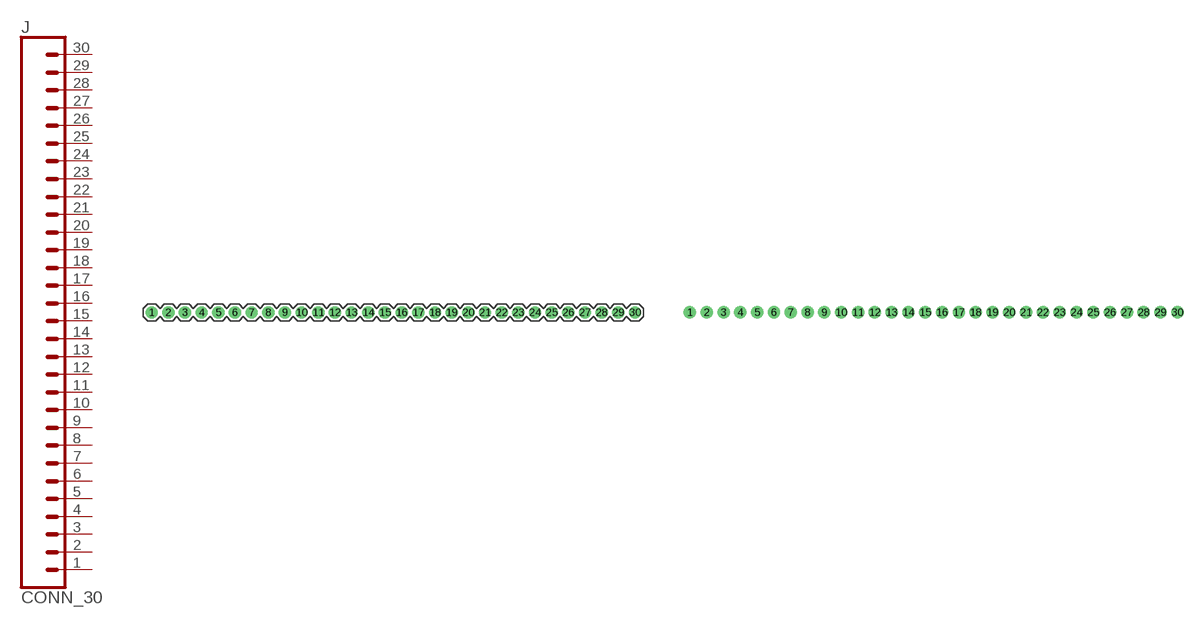
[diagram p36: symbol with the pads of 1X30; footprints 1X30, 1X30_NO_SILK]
Designator prefix J

## CONN_30  [1X30]
1  1  pas
2  2  pas
3  3  pas
4  4  pas
5  5  pas
6  6  pas
7  7  pas
8  8  pas
9  9  pas
10  10  pas
11  11  pas
12  12  pas
13  13  pas
14  14  pas
15  15  pas
16  16  pas
17  17  pas
18  18  pas
19  19  pas
20  20  pas
21  21  pas
22  22  pas
23  23  pas
24  24  pas
25  25  pas
26  26  pas
27  27  pas
28  28  pas
29  29  pas
30  30  pas

## CONN_30NO_SILK  [1X30_NO_SILK]
Pads as for 1X30

## Footprint 1X30 (pad centres in mm)
drill 1.016 pad 1.88: 1 0,0; 2 2.54,0; 3 5.08,0; 4 7.62,0; 5 10.16,0; 6 12.7,0; 7 15.24,0; 8 17.78,0; 9 20.32,0; 10 22.86,0; 11 25.4,0; 12 27.94,0; 13 30.48,0; 14 33.02,0; 15 35.56,0; 16 38.1,0; 17 40.64,0; 18 43.18,0; 19 45.72,0; 20 48.26,0; 21 50.8,0; 22 53.34,0; 23 55.88,0; 24 58.42,0; 25 60.96,0; 26 63.5,0; 27 66.04,0; 28 68.58,0; 29 71.12,0; 30 73.66,0

## Footprint 1X30_NO_SILK (pad centres in mm)
drill 1.016 pad 1.88: 1 0,0; 2 2.54,0; 3 5.08,0; 4 7.62,0; 5 10.16,0; 6 12.7,0; 7 15.24,0; 8 17.78,0; 9 20.32,0; 10 22.86,0; 11 25.4,0; 12 27.94,0; 13 30.48,0; 14 33.02,0; 15 35.56,0; 16 38.1,0; 17 40.64,0; 18 43.18,0; 19 45.72,0; 20 48.26,0; 21 50.8,0; 22 53.34,0; 23 55.88,0; 24 58.42,0; 25 60.96,0; 26 63.5,0; 27 66.04,0; 28 68.58,0; 29 71.12,0; 30 73.66,0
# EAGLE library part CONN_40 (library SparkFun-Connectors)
1x40 .1" header

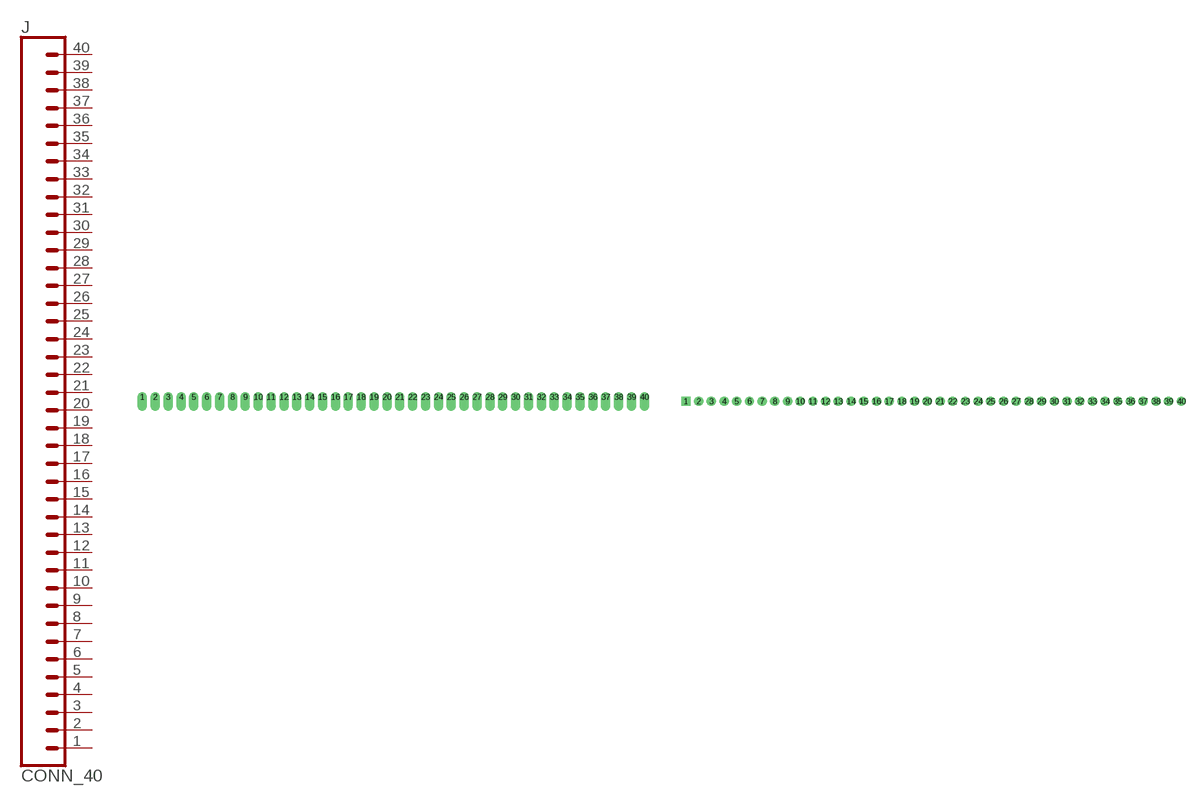
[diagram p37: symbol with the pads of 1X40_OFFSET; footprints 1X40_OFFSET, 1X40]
Designator prefix J

## CONN_40OFFSET  [1X40_OFFSET]
1  1  pas
2  2  pas
3  3  pas
4  4  pas
5  5  pas
6  6  pas
7  7  pas
8  8  pas
9  9  pas
10  10  pas
11  11  pas
12  12  pas
13  13  pas
14  14  pas
15  15  pas
16  16  pas
17  17  pas
18  18  pas
19  19  pas
20  20  pas
21  21  pas
22  22  pas
23  23  pas
24  24  pas
25  25  pas
26  26  pas
27  27  pas
28  28  pas
29  29  pas
30  30  pas
31  31  pas
32  32  pas
33  33  pas
34  34  pas
35  35  pas
36  36  pas
37  37  pas
38  38  pas
39  39  pas
40  40  pas

## CONN_40  [1X40]
Pads as for 1X40_OFFSET

## Footprint 1X40_OFFSET (pad centres in mm)
drill 1.016 pad 1.88 offset: 1 0,0; 2 2.54,0; 3 5.08,0; 4 7.62,0; 5 10.16,0; 6 12.7,0; 7 15.24,0; 8 17.78,0; 9 20.32,0; 10 22.86,0; 11 25.4,0; 12 27.94,0; 13 30.48,0; 14 33.02,0; 15 35.56,0; 16 38.1,0; 17 40.64,0; 18 43.18,0; 19 45.72,0; 20 48.26,0; 21 50.8,0; 22 53.34,0; 23 55.88,0; 24 58.42,0; 25 60.96,0; 26 63.5,0; 27 66.04,0; 28 68.58,0; 29 71.12,0; 30 73.66,0; 31 76.2,0; 32 78.74,0; 33 81.28,0; 34 83.82,0; 35 86.36,0; 36 88.9,0; 37 91.44,0; 38 93.98,0; 39 96.52,0; 40 99.06,0

## Footprint 1X40 (pad centres in mm)
drill 1.016 pad 1.88 square: 1 -49.53,0
drill 1.016 pad 1.88: 2 -46.99,0; 3 -44.45,0; 4 -41.91,0; 5 -39.37,0; 6 -36.83,0; 7 -34.29,0; 8 -31.75,0; 9 -29.21,0; 10 -26.67,0; 11 -24.13,0; 12 -21.59,0; 13 -19.05,0; 14 -16.51,0; 15 -13.97,0; 16 -11.43,0; 17 -8.89,0; 18 -6.35,0; 19 -3.81,0; 20 -1.27,0; 21 1.27,0; 22 3.81,0; 23 6.35,0; 24 8.89,0; 25 11.43,0; 26 13.97,0; 27 16.51,0; 28 19.05,0; 29 21.59,0; 30 24.13,0; 31 26.67,0; 32 29.21,0; 33 31.75,0; 34 34.29,0; 35 36.83,0; 36 39.37,0; 37 41.91,0; 38 44.45,0; 39 46.99,0; 40 49.53,0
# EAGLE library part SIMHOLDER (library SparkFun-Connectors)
SIM Socket Socket for SIM cellular cards. Schematic element and footprint production proven. Spark Fun Electronics SKU : PRT-00548

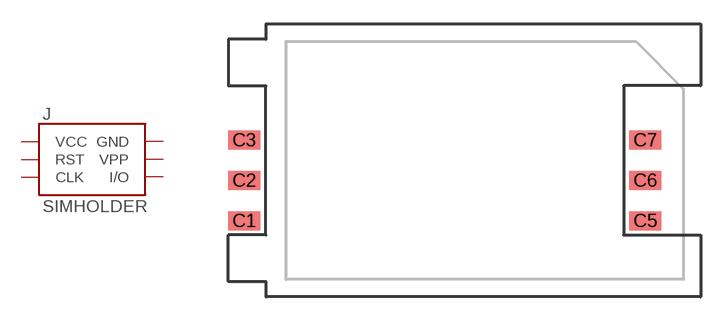
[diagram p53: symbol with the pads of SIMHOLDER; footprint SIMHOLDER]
Designator prefix J

## SIMHOLDERSIM (PROD_ID: CONN-08536)  [SIMHOLDER]
C1  VCC  pwr
C2  RST  in
C3  CLK  in
C5  GND  pwr
C6  VPP  in
C7  I/O

## Footprint SIMHOLDER (pad centres in mm)
smd 2 x 1.2: C1 -12.61,-3.81; C2 -12.61,-1.27; C3 -12.61,1.27; C5 12.61,-3.81; C6 12.61,-1.27; C7 12.61,1.27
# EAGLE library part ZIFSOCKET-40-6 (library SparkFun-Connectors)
Lever-action ZIF socket for 40-pin ICs

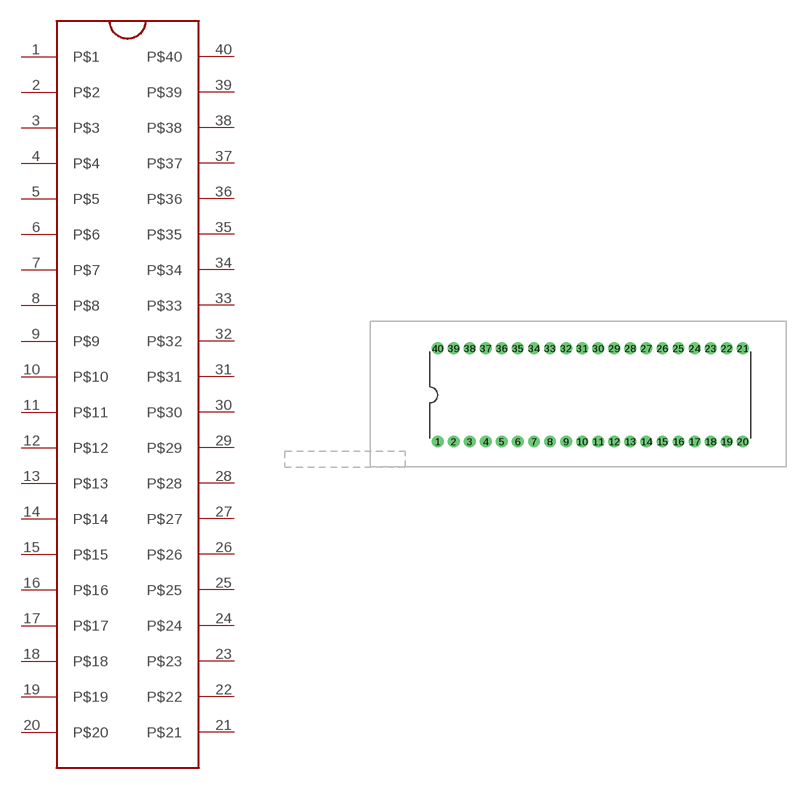
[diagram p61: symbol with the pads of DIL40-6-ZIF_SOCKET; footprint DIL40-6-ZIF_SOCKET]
Designator prefix -

## ZIFSOCKET-40-6DIL40-6-ZIF_SOCKET  [DIL40-6-ZIF_SOCKET]
1  P$1
2  P$2
3  P$3
4  P$4
5  P$5
6  P$6
7  P$7
8  P$8
9  P$9
10  P$10
11  P$11
12  P$12
13  P$13
14  P$14
15  P$15
16  P$16
17  P$17
18  P$18
19  P$19
20  P$20
21  P$21
22  P$22
23  P$23
24  P$24
25  P$25
26  P$26
27  P$27
28  P$28
29  P$29
30  P$30
31  P$31
32  P$32
33  P$33
34  P$34
35  P$35
36  P$36
37  P$37
38  P$38
39  P$39
40  P$40

## Footprint DIL40-6-ZIF_SOCKET (pad centres in mm)
drill 1.016 pad 1.88: 1 -24.13,-7.366; 2 -21.59,-7.366; 3 -19.05,-7.366; 4 -16.51,-7.366; 5 -13.97,-7.366; 6 -11.43,-7.366; 7 -8.89,-7.366; 8 -6.35,-7.366; 9 -3.81,-7.366; 10 -1.27,-7.366; 11 1.27,-7.366; 12 3.81,-7.366; 13 6.35,-7.366; 14 8.89,-7.366; 15 11.43,-7.366; 16 13.97,-7.366; 17 16.51,-7.366; 18 19.05,-7.366; 19 21.59,-7.366; 20 24.13,-7.366; 21 24.13,7.366; 22 21.59,7.366; 23 19.05,7.366; 24 16.51,7.366; 25 13.97,7.366; 26 11.43,7.366; 27 8.89,7.366; 28 6.35,7.366
drill 1.1 pad 1.88: 29 3.81,7.366; 30 1.27,7.366; 31 -1.27,7.366; 32 -3.81,7.366; 33 -6.35,7.366; 34 -8.89,7.366; 35 -11.43,7.366; 36 -13.97,7.366; 37 -16.51,7.366; 38 -19.05,7.366; 39 -21.59,7.366; 40 -24.13,7.366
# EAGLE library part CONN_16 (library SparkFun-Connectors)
1x16 .1" header

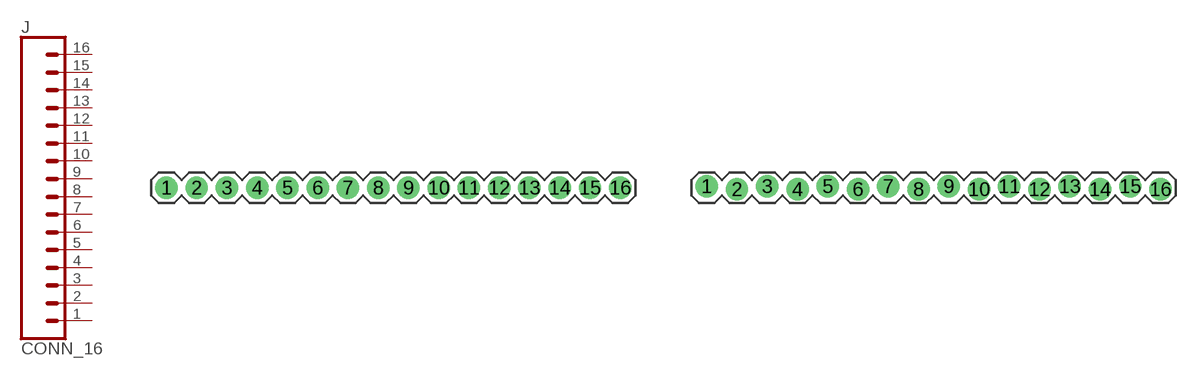
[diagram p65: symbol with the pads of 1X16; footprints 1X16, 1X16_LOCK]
Designator prefix J

## CONN_16PTH  [1X16]
1  1  pas
2  2  pas
3  3  pas
4  4  pas
5  5  pas
6  6  pas
7  7  pas
8  8  pas
9  9  pas
10  10  pas
11  11  pas
12  12  pas
13  13  pas
14  14  pas
15  15  pas
16  16  pas

## CONN_16LOCK  [1X16_LOCK]
Pads as for 1X16

## CONN_16LOCK_LONGPADS  [1X16_LOCK_LONGPADS]
Pads as for 1X16

## CONN_16MACHIINE-PIN_LOCK  [1X16_MACHINE-PIN-HEADER_LOCK.004]
Pads as for 1X16

## CONN_16LONGPADS  [1X16_LONGPADS]
Pads as for 1X16

## CONN_161X16_NO_SILK  [1X16_NO_SILK]
Pads as for 1X16

## Footprint 1X16 (pad centres in mm)
drill 1.016 pad 1.88: 1 0,0; 2 2.54,0; 3 5.08,0; 4 7.62,0; 5 10.16,0; 6 12.7,0; 7 15.24,0; 8 17.78,0; 9 20.32,0; 10 22.86,0; 11 25.4,0; 12 27.94,0; 13 30.48,0; 14 33.02,0; 15 35.56,0; 16 38.1,0

## Footprint 1X16_LOCK (pad centres in mm)
drill 1.016 pad 1.88: 1 0,0.127; 2 2.54,-0.127; 3 5.08,0.127; 4 7.62,-0.127; 5 10.16,0.127; 6 12.7,-0.127; 7 15.24,0.127; 8 17.78,-0.127; 9 20.32,0.127; 10 22.86,-0.127; 11 25.4,0.127; 12 27.94,-0.127; 13 30.48,0.127; 14 33.02,-0.127; 15 35.56,0.127; 16 38.1,-0.127

## Footprint 1X16_LOCK_LONGPADS (pad centres in mm)
drill 1.016 long: 1 0,0.127; 2 2.54,-0.127; 3 5.08,0.127; 4 7.62,-0.127; 5 10.16,0.127; 6 12.7,-0.127; 7 15.24,0.127; 8 17.78,-0.127; 9 20.32,0.127; 10 22.86,-0.127; 11 25.4,0.127; 12 27.94,-0.127; 13 30.48,0.127; 14 33.02,-0.127; 15 35.56,0.127; 16 38.1,-0.127

## Footprint 1X16_MACHINE-PIN-HEADER_LOCK.004 (pad centres in mm)
drill 0.889: 1 0,0.102; 2 2.54,-0.102; 3 5.08,0.102; 4 7.62,-0.102; 5 10.16,0.102; 6 12.7,-0.102; 7 15.24,0.102; 8 17.78,-0.102; 9 20.32,0.102; 10 22.86,-0.102; 11 25.4,0.102; 12 27.94,-0.102; 13 30.48,0.102; 14 33.02,-0.102; 15 35.56,0.102; 16 38.1,-0.102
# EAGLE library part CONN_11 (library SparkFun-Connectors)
Header 11 Standard 11-pin 0.1" header. Use with straight break away headers (SKU : PRT-00116), right angle break away headers (PRT-00553), swiss pins (PRT-00743), machine pins (PRT-00117), and female headers (PRT-00115).

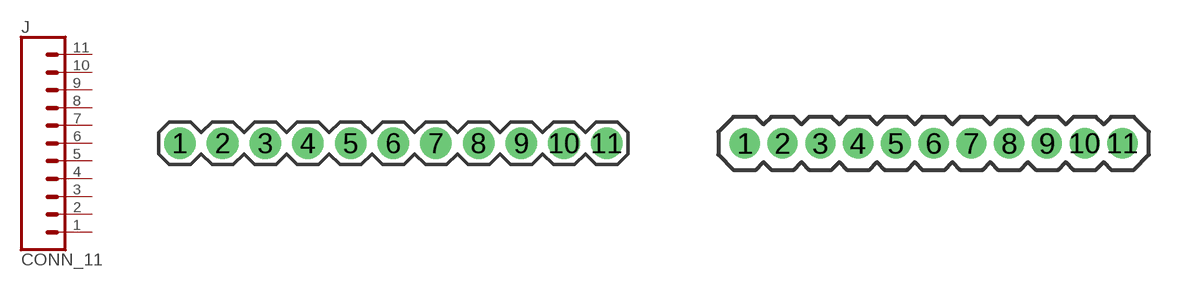
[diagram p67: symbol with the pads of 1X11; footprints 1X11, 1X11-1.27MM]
Designator prefix J

## CONN_11PTH  [1X11]
1  1  pas
2  2  pas
3  3  pas
4  4  pas
5  5  pas
6  6  pas
7  7  pas
8  8  pas
9  9  pas
10  10  pas
11  11  pas

## CONN_111.27MM  [1X11-1.27MM]
Pads as for 1X11

## CONN_11LOCK  [1X11_LOCK]
Pads as for 1X11

## CONN_11LOCK_LONGPADS  [1X11_LOCK_LONGPADS]
Pads as for 1X11

## CONN_11SMD  [1X11_SMD_PTHCOMBO]
Pads as for 1X11

## CONN_11LONGPADS  [1X11_LONGPADS]
Pads as for 1X11

## CONN_11SMD_NO_HOLES  [1X11_SMD_NO_HOLES]
P$1  1  pas
P$2  2  pas
P$3  3  pas
P$4  4  pas
P$5  5  pas
P$6  6  pas
P$7  7  pas
P$8  8  pas
P$9  9  pas
P$10  10  pas
P$11  11  pas

## CONN_11POGOPIN_HOLES_ONLY  [1X11_HOLES_ONLY]
Pads as for 1X11

## CONN_111X11_NO_SILK  [1X11_NO_SILK]
Pads as for 1X11

## CONN_111X11_NO_SILK_KIT  [1X11_NO_SILK_KIT]
Pads as for 1X11

## Footprint 1X11 (pad centres in mm)
drill 1.016 pad 1.88: 1 0,0; 2 2.54,0; 3 5.08,0; 4 7.62,0; 5 10.16,0; 6 12.7,0; 7 15.24,0; 8 17.78,0; 9 20.32,0; 10 22.86,0; 11 25.4,0

## Footprint 1X11-1.27MM (pad centres in mm)
Header for the OS4000-T
drill 0.508 pad 1: 1 0,0; 2 1.27,0; 3 2.54,0; 4 3.81,0; 5 5.08,0; 6 6.35,0; 7 7.62,0; 8 8.89,0; 9 10.16,0; 10 11.43,0; 11 12.7,0

## Footprint 1X11_LOCK (pad centres in mm)
drill 1.016 pad 1.88: 1 0,0.127; 2 2.54,-0.127; 3 5.08,0.127; 4 7.62,-0.127; 5 10.16,0.127; 6 12.7,-0.127; 7 15.24,0.127; 8 17.78,-0.127; 9 20.32,0.127; 10 22.86,-0.127; 11 25.4,0.127

## Footprint 1X11_LOCK_LONGPADS (pad centres in mm)
drill 1.016 long: 1 0,0.127; 2 2.54,-0.127; 3 5.08,0.127; 4 7.62,-0.127; 5 10.16,0.127; 6 12.7,-0.127; 7 15.24,0.127; 8 17.78,-0.127; 9 20.32,0.127; 10 22.86,-0.127; 11 25.4,0.127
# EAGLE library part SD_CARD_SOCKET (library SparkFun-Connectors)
SD Memory Card Connector, push-push normal type, CD enable, WP enable

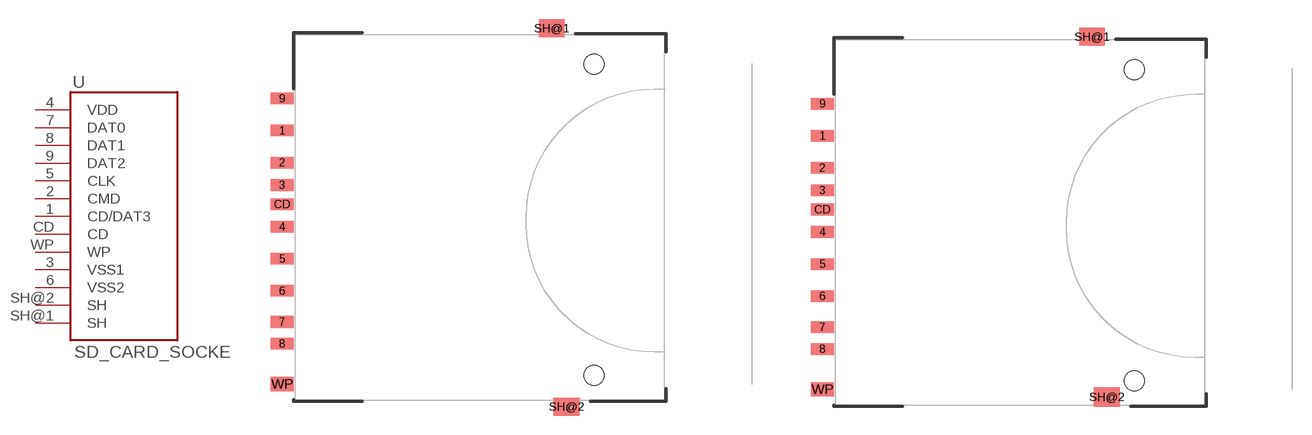
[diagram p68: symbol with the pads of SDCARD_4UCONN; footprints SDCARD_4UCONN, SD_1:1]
Designator prefix U

## SD_CARD_SOCKET4UCON  [SDCARD_4UCONN]
1  CD/DAT3
2  CMD
3  VSS1  pwr
4  VDD  pwr
5  CLK
6  VSS2  pwr
7  DAT0
8  DAT1
9  DAT2
CD  CD
SH@1  SH
SH@2  SH
WP  WP

## SD_CARD_SOCKET  [SD_1:1]
Pads as for SDCARD_4UCONN

## Footprint SDCARD_4UCONN (pad centres in mm)
4UConn part#19646
smd 1.8 x 0.9: 1 -1,6.77; 2 -1,4.27; 3 -1,2.52; 4 -1,-0.73; 5 -1,-3.23; 6 -1,-5.73; 7 -1,-8.15; 8 -1,-9.85; 9 -1,9.27; CD -1,1.02
smd 2 x 1.4: SH@1 20,14.75; SH@2 21.15,-14.75
smd 1.8 x 1.1: WP -1,-13
hole 1.55 at 23.3,11.94
hole 1.55 at 23.3,-12.32

## Footprint SD_1:1 (pad centres in mm)
smd 1.8 x 0.9: 1 -1,6.77; 2 -1,4.27; 3 -1,2.52; 4 -1,-0.73; 5 -1,-3.23; 6 -1,-5.73; 7 -1,-8.15; 8 -1,-9.85; 9 -1,9.27; CD -1,1.02
smd 2 x 1.4: SH@1 20,14.496
smd 2 x 1.527: SH@2 21.15,-13.589
smd 1.8 x 1.1: WP -1,-13
hole 1.55 at 23.3,11.94
hole 1.55 at 23.3,-12.32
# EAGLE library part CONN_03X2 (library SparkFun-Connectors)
2x3 .1" header. Shrouded, with keying- CONN-10681 SMT- CONN-11415 Pogo pins- HW-11044

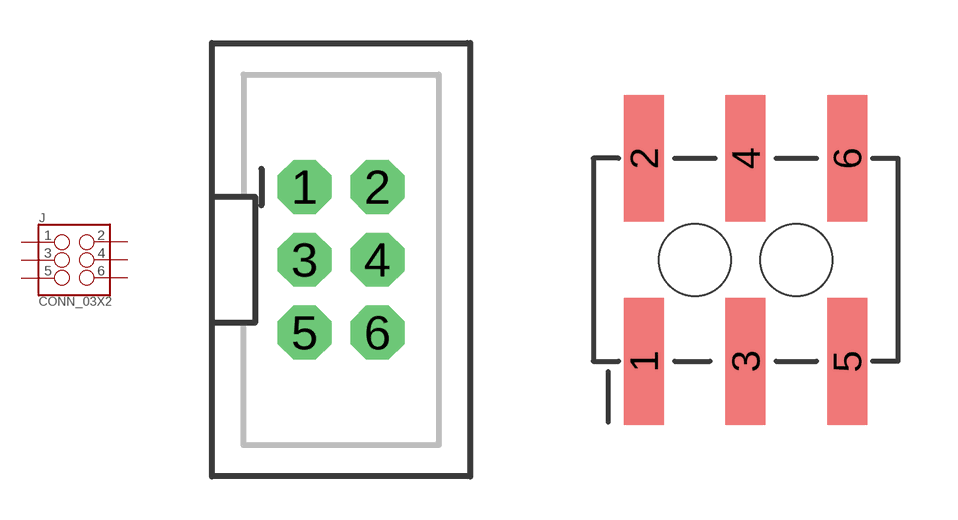
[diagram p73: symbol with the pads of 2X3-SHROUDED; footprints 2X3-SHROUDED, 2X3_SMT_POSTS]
Designator prefix J

## CONN_03X2SHROUD (PROD_ID: CONN-10681)  [2X3-SHROUDED]
1  1
2  2
3  3
4  4
5  5
6  6

## CONN_03X2SMT (PROD_ID: CONN-11415)  [2X3_SMT_POSTS]
Pads as for 2X3-SHROUDED

## CONN_03X2POGO_PINS (PROD_ID: HW-11044)  [2X3_POGO]
P$1  1
P$2  2
P$3  3
P$4  4
P$5  5
P$6  6

## CONN_03X22X3_SILK_MALE_PTH (PROD_ID: CONN-09701)  [2X3]
Pads as for 2X3-SHROUDED

## CONN_03X2NO_SILK  [2X3-NS]
Pads as for 2X3-SHROUDED

## CONN_03X2FEMALE_SMD (PROD_ID: CONN-11290)  [2X3_SMD]
Pads as for 2X3-SHROUDED

## CONN_03X2 (PROD_ID: CONN-11290)  [2X3_SMD]
Pads as for 2X3-SHROUDED

## CONN_03X2FEMALE (PROD_ID: CONN-11566; VALUE: FEMALE 2x3)  [2X3]
Pads as for 2X3-SHROUDED

## Footprint 2X3-SHROUDED (pad centres in mm)
drill 1.016 pad 1.88 octagon: 1 -1.27,2.54; 2 1.27,2.54; 3 -1.27,0; 4 1.27,0; 5 -1.27,-2.54; 6 1.27,-2.54

## Footprint 2X3_SMT_POSTS (pad centres in mm)
4UCON 15881 Male .1" spaced SMT Keying posts into board
smd 1 x 3.17: 1 -2.54,-2.54; 2 -2.54,2.54; 3 0,-2.54; 4 0,2.54; 5 2.54,-2.54; 6 2.54,2.54
hole 1.8 at -1.27,0
hole 1.8 at 1.27,0

## Footprint 2X3_POGO (pad centres in mm)
drill 1.2 pad 1.829 octagon: P$1 0,0; P$2 0,2.54; P$3 2.54,0; P$4 2.54,2.54; P$5 5.08,0; P$6 5.08,2.54

## Footprint 2X3 (pad centres in mm)
drill 1.016 pad 1.88 octagon: 1 0,0; 2 0,2.54; 3 2.54,0; 4 2.54,2.54; 5 5.08,0; 6 5.08,2.54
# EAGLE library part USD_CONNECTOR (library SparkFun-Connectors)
microSD Socket Push-push type µSD socket. Footprint production proven. Symbol has new and improved layout and naming accuracy. SparkFun Electronics SKU : PRT-00127. tDoc lines correctly indicate media card edge positions when inserting (unlocked, locked, depressed). NOTE: CD1 and CD2 are connected internally

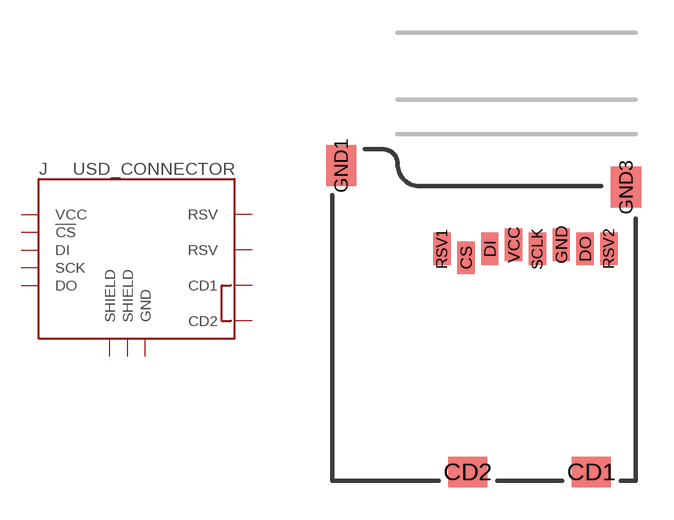
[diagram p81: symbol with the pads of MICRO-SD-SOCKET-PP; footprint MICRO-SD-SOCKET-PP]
Designator prefix J

## USD_CONNECTOR (PROD_ID: CONN-07820)  [MICRO-SD-SOCKET-PP]
CD1  CD1
CD2  CD2
CS  !CS
DI  DI
DO  DO
GND  GND
GND1  SHIELD
GND3  SHIELD
RSV1  RSV
RSV2  RSV
SCLK  SCK
VCC  VCC

## Footprint MICRO-SD-SOCKET-PP (pad centres in mm)
smd 1.8 x 1.4: CD1 -2.05,0.4; CD2 -7.75,0.4
smd 0.8 x 1.5: CS -7.84,10.3; DI -6.74,10.7; DO -2.34,10.7; GND -3.44,10.9; RSV1 -8.94,10.7; RSV2 -1.24,10.7; SCLK -4.54,10.7; VCC -5.64,10.9
smd 1.4 x 1.9: GND1 -13.6,14.55; GND3 -0.45,13.55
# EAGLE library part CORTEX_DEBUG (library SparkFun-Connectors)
Cortex Debug Connector Datasheet

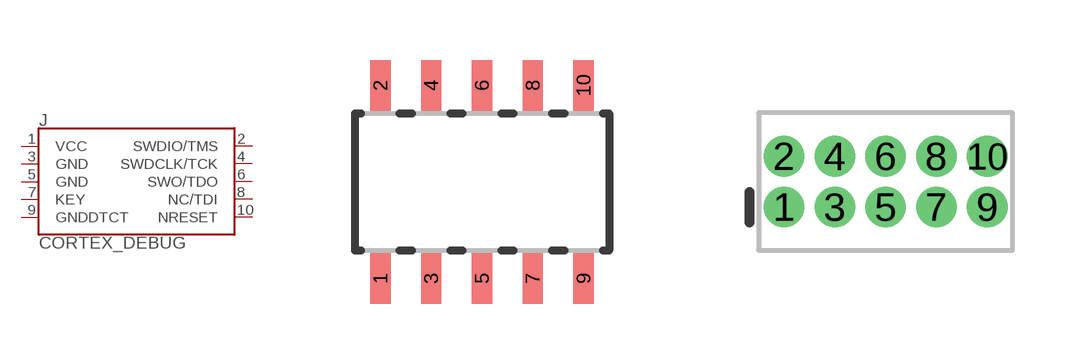
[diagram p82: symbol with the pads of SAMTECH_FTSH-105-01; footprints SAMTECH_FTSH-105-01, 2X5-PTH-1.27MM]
Designator prefix J

## CORTEX_DEBUGSMD  [SAMTECH_FTSH-105-01]
1  VCC
2  SWDIO/TMS
3  GND
4  SWDCLK/TCK
5  GND
6  SWO/TDO
7  KEY
8  NC/TDI
9  GNDDTCT
10  NRESET

## CORTEX_DEBUGPTH  [2X5-PTH-1.27MM]
Pads as for SAMTECH_FTSH-105-01

## Footprint SAMTECH_FTSH-105-01 (pad centres in mm)
2x5 Connector (Cortex Debug Connector) Datasheet
smd 0.508 x 1.27: 1 -2.54,-2.413; 2 -2.54,2.413; 3 -1.27,-2.413; 4 -1.27,2.413; 5 0,-2.413; 6 0,2.413; 7 1.27,-2.413; 8 1.27,2.413; 9 2.54,-2.413; 10 2.54,2.413

## Footprint 2X5-PTH-1.27MM (pad centres in mm)
ARM Cortex Debug Connector (10-pin) For debuggers and/or programemrs that support the Cortex Debug Connector (10-pin) interface. tDoc (51) layer border represents maximum dimensions of plastic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
drill 0.508 pad 1: 1 -2.54,-0.635; 2 -2.54,0.635; 3 -1.27,-0.635; 4 -1.27,0.635; 5 0,-0.635; 6 0,0.635; 7 1.27,-0.635; 8 1.27,0.635; 9 2.54,-0.635; 10 2.54,0.635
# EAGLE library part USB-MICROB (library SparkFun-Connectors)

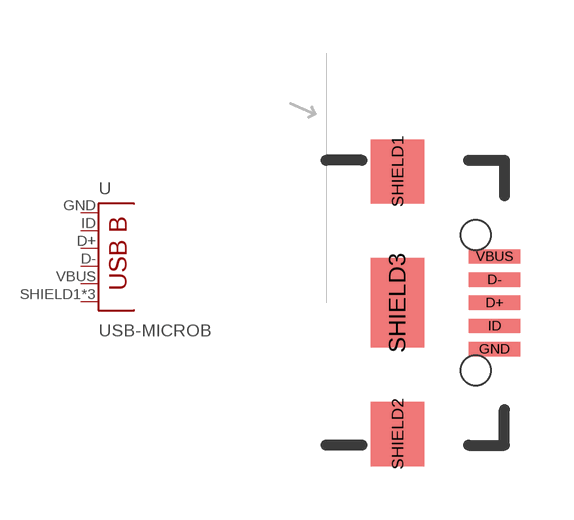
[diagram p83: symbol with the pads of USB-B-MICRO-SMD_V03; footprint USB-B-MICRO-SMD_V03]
Designator prefix -

## USB-MICROB" (PROD_ID: CONN-11752)  [USB-B-MICRO-SMD_V03]
D+  D+
D-  D-
GND  GND
ID  USBID
SHIELD1  SHIELD
SHIELD2  SHIELD
SHIELD3  SHIELD
VBUS  VBUS

## Footprint USB-B-MICRO-SMD_V03 (pad centres in mm)
smd 1.45 x 0.4: D+ 2.725,0; D- 2.725,0.65; GND 2.725,-1.3; ID 2.725,-0.65; VBUS 2.725,1.3
smd 1.5 x 1.8: SHIELD1 0,3.685; SHIELD2 0,-3.685
smd 1.5 x 2.5: SHIELD3 0,0
hole 0.85 at 2.2,1.9
hole 0.85 at 2.2,-1.9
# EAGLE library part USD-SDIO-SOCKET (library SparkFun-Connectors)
microSD Socket Push-push type uSD socket with full SDIO signal mapping. Spark Fun Electronics SKU : PRT-00127. tDoc lines correctly indicate media card edge positions when inserting (unlocked, locked, depressed). NOTE: CD1 and CD2 are connected internally, and short to ground when card is removed.

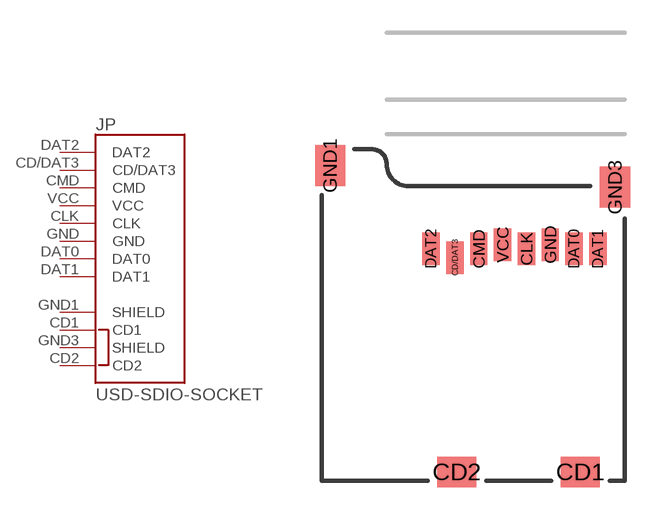
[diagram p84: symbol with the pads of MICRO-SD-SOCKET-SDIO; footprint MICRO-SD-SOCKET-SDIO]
Designator prefix JP

## USD-SDIO-SOCKET (PROD_ID: CONN-07820)  [MICRO-SD-SOCKET-SDIO]
CD1  CD1
CD2  CD2
CD/DAT3  CD/DAT3
CLK  CLK
CMD  CMD
DAT0  DAT0
DAT1  DAT1
DAT2  DAT2
GND  GND
GND1  SHIELD
GND3  SHIELD
VCC  VCC

## Footprint MICRO-SD-SOCKET-SDIO (pad centres in mm)
smd 1.8 x 1.4: CD1 11.92,0.4; CD2 6.22,0.4
smd 0.8 x 1.5: CD/DAT3 6.13,10.3; CLK 9.43,10.7; CMD 7.23,10.7; DAT0 11.63,10.7; DAT1 12.73,10.7; DAT2 5.03,10.7; GND 10.53,10.9; VCC 8.33,10.9
smd 1.4 x 1.9: GND1 0.37,14.55; GND3 13.52,13.55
